VERSION 5.8 ;
BUSBITCHARS "[]" ;
DIVIDERCHAR "/" ;
UNITS
    DATABASE MICRONS 2000 ;
END UNITS

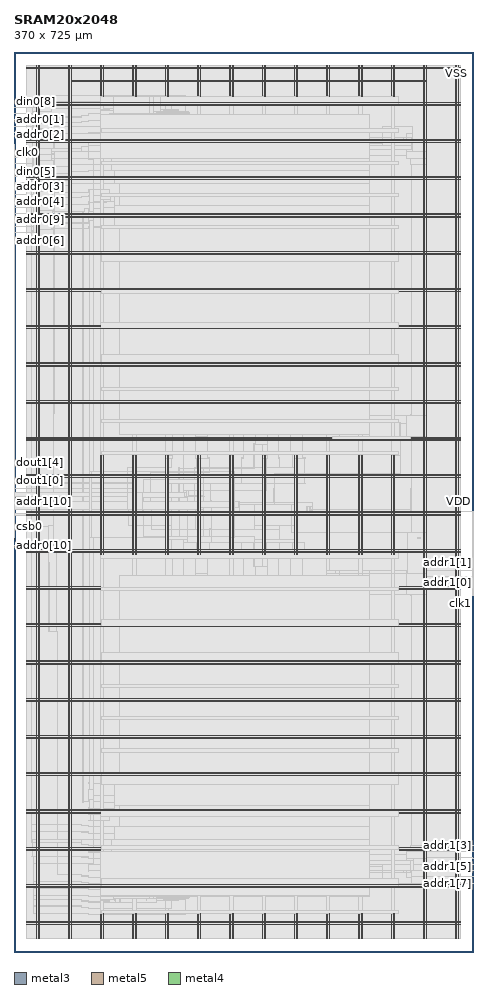
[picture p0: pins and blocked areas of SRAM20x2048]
MACRO SRAM20x2048
  FOREIGN SRAM20x2048 0 0 ;
  CLASS BLOCK ;
  SIZE 370 BY 725 ;
  PIN addr0[0]
    DIRECTION INPUT ;
    USE SIGNAL ;
    PORT
      LAYER metal3 ;
        RECT  0 614.915 0.07 614.985 ;
    END
  END addr0[0]
  PIN addr0[10]
    DIRECTION INPUT ;
    USE SIGNAL ;
    PORT
      LAYER metal3 ;
        RECT  0 327.635 0.07 327.705 ;
    END
  END addr0[10]
  PIN addr0[1]
    DIRECTION INPUT ;
    USE SIGNAL ;
    PORT
      LAYER metal3 ;
        RECT  0 670.355 0.07 670.425 ;
    END
  END addr0[1]
  PIN addr0[2]
    DIRECTION INPUT ;
    USE SIGNAL ;
    PORT
      LAYER metal3 ;
        RECT  0 665.315 0.07 665.385 ;
    END
  END addr0[2]
  PIN addr0[3]
    DIRECTION INPUT ;
    USE SIGNAL ;
    PORT
      LAYER metal3 ;
        RECT  0 609.875 0.07 609.945 ;
    END
  END addr0[3]
  PIN addr0[4]
    DIRECTION INPUT ;
    USE SIGNAL ;
    PORT
      LAYER metal3 ;
        RECT  0 604.835 0.07 604.905 ;
    END
  END addr0[4]
  PIN addr0[5]
    DIRECTION INPUT ;
    USE SIGNAL ;
    PORT
      LAYER metal3 ;
        RECT  0 599.795 0.07 599.865 ;
    END
  END addr0[5]
  PIN addr0[6]
    DIRECTION INPUT ;
    USE SIGNAL ;
    PORT
      LAYER metal3 ;
        RECT  0 579.635 0.07 579.705 ;
    END
  END addr0[6]
  PIN addr0[7]
    DIRECTION INPUT ;
    USE SIGNAL ;
    PORT
      LAYER metal3 ;
        RECT  0 594.755 0.07 594.825 ;
    END
  END addr0[7]
  PIN addr0[8]
    DIRECTION INPUT ;
    USE SIGNAL ;
    PORT
      LAYER metal3 ;
        RECT  0 584.675 0.07 584.745 ;
    END
  END addr0[8]
  PIN addr0[9]
    DIRECTION INPUT ;
    USE SIGNAL ;
    PORT
      LAYER metal3 ;
        RECT  0 589.715 0.07 589.785 ;
    END
  END addr0[9]
  PIN addr1[0]
    DIRECTION INPUT ;
    USE SIGNAL ;
    PORT
      LAYER metal3 ;
        RECT  369.93 297.395 370 297.465 ;
    END
  END addr1[0]
  PIN addr1[10]
    DIRECTION INPUT ;
    USE SIGNAL ;
    PORT
      LAYER metal3 ;
        RECT  0 362.915 0.07 362.985 ;
    END
  END addr1[10]
  PIN addr1[1]
    DIRECTION INPUT ;
    USE SIGNAL ;
    PORT
      LAYER metal3 ;
        RECT  369.93 307.475 370 307.545 ;
    END
  END addr1[1]
  PIN addr1[2]
    DIRECTION INPUT ;
    USE SIGNAL ;
    PORT
      LAYER metal3 ;
        RECT  369.93 302.435 370 302.505 ;
    END
  END addr1[2]
  PIN addr1[3]
    DIRECTION INPUT ;
    USE SIGNAL ;
    PORT
      LAYER metal3 ;
        RECT  369.93 85.715 370 85.785 ;
    END
  END addr1[3]
  PIN addr1[4]
    DIRECTION INPUT ;
    USE SIGNAL ;
    PORT
      LAYER metal3 ;
        RECT  369.93 80.675 370 80.745 ;
    END
  END addr1[4]
  PIN addr1[5]
    DIRECTION INPUT ;
    USE SIGNAL ;
    PORT
      LAYER metal3 ;
        RECT  369.93 75.635 370 75.705 ;
    END
  END addr1[5]
  PIN addr1[6]
    DIRECTION INPUT ;
    USE SIGNAL ;
    PORT
      LAYER metal3 ;
        RECT  369.93 70.595 370 70.665 ;
    END
  END addr1[6]
  PIN addr1[7]
    DIRECTION INPUT ;
    USE SIGNAL ;
    PORT
      LAYER metal3 ;
        RECT  369.93 55.475 370 55.545 ;
    END
  END addr1[7]
  PIN addr1[8]
    DIRECTION INPUT ;
    USE SIGNAL ;
    PORT
      LAYER metal3 ;
        RECT  369.93 65.555 370 65.625 ;
    END
  END addr1[8]
  PIN addr1[9]
    DIRECTION INPUT ;
    USE SIGNAL ;
    PORT
      LAYER metal3 ;
        RECT  369.93 60.515 370 60.585 ;
    END
  END addr1[9]
  PIN clk0
    DIRECTION INPUT ;
    USE SIGNAL ;
    PORT
      LAYER metal3 ;
        RECT  0 650.195 0.07 650.265 ;
    END
  END clk0
  PIN clk1
    DIRECTION INPUT ;
    USE SIGNAL ;
    PORT
      LAYER metal3 ;
        RECT  369.93 287.315 370 287.385 ;
    END
  END clk1
  PIN csb0
    DIRECTION INPUT ;
    USE SIGNAL ;
    PORT
      LAYER metal3 ;
        RECT  0 342.755 0.07 342.825 ;
    END
  END csb0
  PIN csb1
    DIRECTION INPUT ;
    USE SIGNAL ;
    PORT
      LAYER metal3 ;
        RECT  0 357.875 0.07 357.945 ;
    END
  END csb1
  PIN din0[0]
    DIRECTION INPUT ;
    USE SIGNAL ;
    PORT
      LAYER metal3 ;
        RECT  0 675.395 0.07 675.465 ;
    END
  END din0[0]
  PIN din0[1]
    DIRECTION INPUT ;
    USE SIGNAL ;
    PORT
      LAYER metal3 ;
        RECT  0 660.275 0.07 660.345 ;
    END
  END din0[1]
  PIN din0[2]
    DIRECTION INPUT ;
    USE SIGNAL ;
    PORT
      LAYER metal3 ;
        RECT  0 645.155 0.07 645.225 ;
    END
  END din0[2]
  PIN din0[3]
    DIRECTION INPUT ;
    USE SIGNAL ;
    PORT
      LAYER metal3 ;
        RECT  0 640.115 0.07 640.185 ;
    END
  END din0[3]
  PIN din0[4]
    DIRECTION INPUT ;
    USE SIGNAL ;
    PORT
      LAYER metal3 ;
        RECT  0 680.435 0.07 680.505 ;
    END
  END din0[4]
  PIN din0[5]
    DIRECTION INPUT ;
    USE SIGNAL ;
    PORT
      LAYER metal3 ;
        RECT  0 635.075 0.07 635.145 ;
    END
  END din0[5]
  PIN din0[6]
    DIRECTION INPUT ;
    USE SIGNAL ;
    PORT
      LAYER metal3 ;
        RECT  0 630.035 0.07 630.105 ;
    END
  END din0[6]
  PIN din0[7]
    DIRECTION INPUT ;
    USE SIGNAL ;
    PORT
      LAYER metal3 ;
        RECT  0 624.995 0.07 625.065 ;
    END
  END din0[7]
  PIN din0[8]
    DIRECTION INPUT ;
    USE SIGNAL ;
    PORT
      LAYER metal3 ;
        RECT  0 685.475 0.07 685.545 ;
    END
  END din0[8]
  PIN din0[9]
    DIRECTION INPUT ;
    USE SIGNAL ;
    PORT
      LAYER metal3 ;
        RECT  0 619.955 0.07 620.025 ;
    END
  END din0[9]
  PIN dout1[0]
    DIRECTION OUTPUT ;
    USE SIGNAL ;
    PORT
      LAYER metal3 ;
        RECT  0 372.995 0.07 373.065 ;
    END
  END dout1[0]
  PIN dout1[1]
    DIRECTION OUTPUT ;
    USE SIGNAL ;
    PORT
      LAYER metal3 ;
        RECT  0 378.035 0.07 378.105 ;
    END
  END dout1[1]
  PIN dout1[2]
    DIRECTION OUTPUT ;
    USE SIGNAL ;
    PORT
      LAYER metal3 ;
        RECT  0 332.675 0.07 332.745 ;
    END
  END dout1[2]
  PIN dout1[3]
    DIRECTION OUTPUT ;
    USE SIGNAL ;
    PORT
      LAYER metal3 ;
        RECT  0 352.835 0.07 352.905 ;
    END
  END dout1[3]
  PIN dout1[4]
    DIRECTION OUTPUT ;
    USE SIGNAL ;
    PORT
      LAYER metal3 ;
        RECT  0 388.115 0.07 388.185 ;
    END
  END dout1[4]
  PIN dout1[5]
    DIRECTION OUTPUT ;
    USE SIGNAL ;
    PORT
      LAYER metal3 ;
        RECT  0 337.715 0.07 337.785 ;
    END
  END dout1[5]
  PIN dout1[6]
    DIRECTION OUTPUT ;
    USE SIGNAL ;
    PORT
      LAYER metal3 ;
        RECT  0 393.155 0.07 393.225 ;
    END
  END dout1[6]
  PIN dout1[7]
    DIRECTION OUTPUT ;
    USE SIGNAL ;
    PORT
      LAYER metal3 ;
        RECT  0 347.795 0.07 347.865 ;
    END
  END dout1[7]
  PIN dout1[8]
    DIRECTION OUTPUT ;
    USE SIGNAL ;
    PORT
      LAYER metal3 ;
        RECT  0 383.075 0.07 383.145 ;
    END
  END dout1[8]
  PIN dout1[9]
    DIRECTION OUTPUT ;
    USE SIGNAL ;
    PORT
      LAYER metal3 ;
        RECT  0 367.955 0.07 368.025 ;
    END
  END dout1[9]
  PIN VSS
    DIRECTION INOUT ;
    USE GROUND ;
    PORT
      LAYER metal5 ;
        RECT  310.43 531.95 359.86 532.45 ;
        RECT  310.43 291.95 359.86 292.45 ;
        RECT  310.43 111.95 359.86 112.45 ;
        RECT  310.43 81.95 359.86 82.45 ;
        RECT  10.07 711.95 359.86 712.45 ;
        RECT  10.07 681.95 359.86 682.45 ;
        RECT  10.07 651.95 359.86 652.45 ;
        RECT  10.07 621.95 359.86 622.45 ;
        RECT  10.07 591.95 359.86 592.45 ;
        RECT  10.07 561.95 359.86 562.45 ;
        RECT  10.07 531.95 69.32 532.45 ;
        RECT  10.07 501.95 359.86 502.45 ;
        RECT  10.07 471.95 359.86 472.45 ;
        RECT  10.07 441.95 359.86 442.45 ;
        RECT  10.07 411.95 359.86 412.45 ;
        RECT  10.07 381.95 359.86 382.45 ;
        RECT  10.07 351.95 359.86 352.45 ;
        RECT  10.07 321.95 359.86 322.45 ;
        RECT  10.07 291.95 69.32 292.45 ;
        RECT  10.07 261.95 359.86 262.45 ;
        RECT  10.07 231.95 359.86 232.45 ;
        RECT  10.07 201.95 359.86 202.45 ;
        RECT  10.07 171.95 359.86 172.45 ;
        RECT  10.07 141.95 359.86 142.45 ;
        RECT  10.07 111.95 69.57 112.45 ;
        RECT  10.07 81.95 69.32 82.45 ;
        RECT  10.07 51.95 359.86 52.45 ;
        RECT  10.07 21.95 359.86 22.45 ;
      LAYER metal4 ;
        RECT  355.82 11.13 356.32 714.07 ;
        RECT  329.82 11.13 330.32 714.07 ;
        RECT  303.82 689.59 304.32 714.07 ;
        RECT  303.82 320.23 304.32 399.79 ;
        RECT  303.82 11.13 304.32 30.43 ;
        RECT  277.82 689.59 278.32 714.07 ;
        RECT  277.82 320.23 278.32 399.79 ;
        RECT  277.82 11.13 278.32 30.43 ;
        RECT  251.82 689.59 252.32 714.07 ;
        RECT  251.82 320.23 252.32 399.79 ;
        RECT  251.82 11.13 252.32 30.43 ;
        RECT  225.82 689.59 226.32 714.07 ;
        RECT  225.82 320.23 226.32 399.79 ;
        RECT  225.82 11.13 226.32 30.43 ;
        RECT  199.82 689.59 200.32 714.07 ;
        RECT  199.82 320.23 200.32 399.79 ;
        RECT  199.82 11.13 200.32 30.43 ;
        RECT  173.82 689.59 174.32 714.07 ;
        RECT  173.82 320.23 174.32 399.79 ;
        RECT  173.82 11.13 174.32 30.43 ;
        RECT  147.82 689.59 148.32 714.07 ;
        RECT  147.82 320.23 148.32 399.79 ;
        RECT  147.82 11.13 148.32 30.43 ;
        RECT  121.82 689.59 122.32 714.07 ;
        RECT  121.82 320.23 122.32 399.79 ;
        RECT  121.82 11.13 122.32 30.43 ;
        RECT  95.82 689.59 96.32 714.07 ;
        RECT  95.82 320.23 96.32 399.79 ;
        RECT  95.82 11.13 96.32 30.43 ;
        RECT  69.82 689.59 70.32 714.07 ;
        RECT  69.82 320.23 70.32 399.79 ;
        RECT  69.82 11.13 70.32 30.43 ;
        RECT  43.82 11.13 44.32 714.07 ;
        RECT  17.82 11.13 18.32 714.07 ;
    END
  END VSS
  PIN VDD
    DIRECTION INOUT ;
    USE POWER ;
    PORT
      LAYER metal5 ;
        RECT  45.92 701.5 332.42 702 ;
        RECT  320.175 414.05 359.86 414.55 ;
        RECT  310.43 504.05 359.86 504.55 ;
        RECT  310.43 294.05 359.86 294.55 ;
        RECT  310.43 264.05 359.86 264.55 ;
        RECT  310.43 84.05 359.86 84.55 ;
        RECT  10.07 684.05 359.86 684.55 ;
        RECT  10.07 654.05 359.86 654.55 ;
        RECT  10.07 624.05 359.86 624.55 ;
        RECT  10.07 594.05 359.86 594.55 ;
        RECT  10.07 564.05 359.86 564.55 ;
        RECT  10.07 534.05 359.86 534.55 ;
        RECT  10.07 504.05 69.57 504.55 ;
        RECT  10.07 474.05 359.86 474.55 ;
        RECT  10.07 444.05 359.86 444.55 ;
        RECT  10.07 414.05 255.935 414.55 ;
        RECT  10.07 384.05 359.86 384.55 ;
        RECT  10.07 354.05 359.86 354.55 ;
        RECT  10.07 324.05 359.86 324.55 ;
        RECT  10.07 294.05 69.57 294.55 ;
        RECT  10.07 264.05 69.32 264.55 ;
        RECT  10.07 234.05 359.86 234.55 ;
        RECT  10.07 204.05 359.86 204.55 ;
        RECT  10.07 174.05 359.86 174.55 ;
        RECT  10.07 144.05 359.86 144.55 ;
        RECT  10.07 114.05 359.86 114.55 ;
        RECT  10.07 84.05 69.57 84.55 ;
        RECT  10.07 54.05 359.86 54.55 ;
        RECT  10.07 24.05 359.86 24.55 ;
      LAYER metal4 ;
        RECT  357.92 11.16 358.42 714.04 ;
        RECT  331.92 11.16 332.42 714.04 ;
        RECT  305.92 689.38 306.42 714.04 ;
        RECT  305.92 320.2 306.42 399.82 ;
        RECT  305.92 11.16 306.42 30.64 ;
        RECT  279.92 689.38 280.42 714.04 ;
        RECT  279.92 320.2 280.42 399.82 ;
        RECT  279.92 11.16 280.42 30.64 ;
        RECT  253.92 689.38 254.42 714.04 ;
        RECT  253.92 320.2 254.42 399.82 ;
        RECT  253.92 11.16 254.42 30.64 ;
        RECT  227.92 689.38 228.42 714.04 ;
        RECT  227.92 320.2 228.42 399.82 ;
        RECT  227.92 11.16 228.42 30.64 ;
        RECT  201.92 689.38 202.42 714.04 ;
        RECT  201.92 320.2 202.42 399.82 ;
        RECT  201.92 11.16 202.42 30.64 ;
        RECT  175.92 689.38 176.42 714.04 ;
        RECT  175.92 320.2 176.42 399.82 ;
        RECT  175.92 11.16 176.42 30.64 ;
        RECT  149.92 689.38 150.42 714.04 ;
        RECT  149.92 320.2 150.42 399.82 ;
        RECT  149.92 11.16 150.42 30.64 ;
        RECT  123.92 689.38 124.42 714.04 ;
        RECT  123.92 320.2 124.42 399.82 ;
        RECT  123.92 11.16 124.42 30.64 ;
        RECT  97.92 689.38 98.42 714.04 ;
        RECT  97.92 320.2 98.42 399.82 ;
        RECT  97.92 11.16 98.42 30.64 ;
        RECT  71.92 689.38 72.42 714.04 ;
        RECT  71.92 320.2 72.42 399.82 ;
        RECT  71.92 11.16 72.42 30.64 ;
        RECT  45.92 11.16 46.42 714.04 ;
        RECT  19.92 11.16 20.42 714.04 ;
    END
  END VDD
  OBS
    LAYER metal1 ;
     RECT  10.07 11.115 359.86 714.085 ;
    LAYER metal2 ;
     RECT  17.84 11.13 18.3 12.53 ;
     RECT  43.84 11.13 44.3 12.53 ;
     RECT  69.84 11.13 70.3 12.53 ;
     RECT  95.84 11.13 96.3 12.53 ;
     RECT  121.84 11.13 122.3 12.53 ;
     RECT  147.84 11.13 148.3 12.53 ;
     RECT  173.84 11.13 174.3 12.53 ;
     RECT  199.84 11.13 200.3 12.53 ;
     RECT  225.84 11.13 226.3 12.53 ;
     RECT  251.84 11.13 252.3 12.53 ;
     RECT  277.84 11.13 278.3 12.53 ;
     RECT  303.84 11.13 304.3 12.53 ;
     RECT  329.84 11.13 330.3 12.53 ;
     RECT  355.84 11.13 356.3 12.53 ;
     RECT  69.84 12.53 72.4 28.07 ;
     RECT  95.84 12.53 98.4 28.07 ;
     RECT  121.84 12.53 124.4 28.07 ;
     RECT  147.84 12.53 150.4 28.07 ;
     RECT  173.84 12.53 176.4 28.07 ;
     RECT  199.84 12.53 202.4 28.07 ;
     RECT  225.84 12.53 228.4 28.07 ;
     RECT  251.84 12.53 254.4 28.07 ;
     RECT  277.84 12.53 280.4 28.07 ;
     RECT  303.84 12.53 306.4 28.07 ;
     RECT  17.84 12.53 20.4 31.22 ;
     RECT  69.88 28.07 72.4 32.55 ;
     RECT  95.88 28.07 98.4 32.55 ;
     RECT  121.88 28.07 124.4 32.55 ;
     RECT  147.88 28.07 150.4 32.55 ;
     RECT  173.88 28.07 176.4 32.55 ;
     RECT  199.88 28.07 202.4 32.55 ;
     RECT  225.88 28.07 228.4 32.55 ;
     RECT  251.88 28.07 254.4 32.55 ;
     RECT  277.88 28.07 280.4 32.55 ;
     RECT  303.88 28.07 306.4 32.55 ;
     RECT  69.88 32.55 72.44 42.49 ;
     RECT  95.88 32.55 98.44 45.16 ;
     RECT  121.88 32.55 124.44 45.16 ;
     RECT  147.88 32.55 150.44 45.16 ;
     RECT  173.88 32.55 176.44 45.16 ;
     RECT  199.88 32.55 202.44 45.16 ;
     RECT  225.88 32.55 228.44 45.16 ;
     RECT  251.88 32.55 254.44 45.16 ;
     RECT  277.88 32.55 280.44 45.16 ;
     RECT  15.64 31.22 20.4 76.72 ;
     RECT  320.02 77 320.47 85.96 ;
     RECT  14.5 76.72 20.4 87.92 ;
     RECT  34.83 62.58 34.9 258.16 ;
     RECT  34.45 258.16 34.9 258.3 ;
     RECT  320.02 85.96 320.09 293.02 ;
     RECT  319.83 293.02 320.09 299.18 ;
     RECT  319.83 299.18 320.66 301.98 ;
     RECT  85.415 45.16 286.08 303.37 ;
     RECT  70.165 42.49 72.44 305.55 ;
     RECT  316.79 301.98 320.66 307.86 ;
     RECT  28.18 258.16 28.25 313.88 ;
     RECT  69.88 305.55 72.44 318.29 ;
     RECT  95.88 303.37 98.44 318.29 ;
     RECT  147.88 303.37 150.44 318.29 ;
     RECT  173.88 303.37 176.44 318.29 ;
     RECT  225.88 303.37 228.44 318.29 ;
     RECT  251.88 303.37 254.44 318.29 ;
     RECT  277.88 303.37 280.44 318.29 ;
     RECT  303.88 32.55 306.44 318.29 ;
     RECT  225.88 318.29 228.4 319.2 ;
     RECT  69.88 318.29 72.4 321.93 ;
     RECT  95.88 318.29 98.4 321.93 ;
     RECT  121.88 303.37 124.44 321.93 ;
     RECT  147.88 318.29 150.4 321.93 ;
     RECT  173.88 318.29 176.4 321.93 ;
     RECT  199.88 303.37 202.44 321.93 ;
     RECT  251.88 318.29 254.4 321.93 ;
     RECT  277.88 318.29 280.4 321.93 ;
     RECT  303.88 318.29 306.4 321.93 ;
     RECT  121.84 321.93 124.44 322 ;
     RECT  147.84 321.93 150.4 322 ;
     RECT  199.84 321.93 202.44 322 ;
     RECT  27.99 314.16 28.06 327.32 ;
     RECT  34.45 258.3 34.52 327.32 ;
     RECT  27.99 327.32 34.52 327.74 ;
     RECT  234.33 322 234.4 329.95 ;
     RECT  157.38 322 157.45 329.98 ;
     RECT  234.14 329.95 234.4 330.02 ;
     RECT  136.86 319.2 136.93 330.12 ;
     RECT  234.14 330.02 234.21 330.12 ;
     RECT  199.84 322 203.62 330.26 ;
     RECT  325.53 287.14 325.6 330.82 ;
     RECT  147.12 322 150.4 331.94 ;
     RECT  121.84 322 126.67 332.08 ;
     RECT  224.07 319.2 228.4 332.08 ;
     RECT  183.03 322 183.1 332.22 ;
     RECT  320.02 307.86 320.66 333.415 ;
     RECT  173.84 321.93 176.4 333.48 ;
     RECT  325.15 330.96 325.22 333.48 ;
     RECT  173.84 333.48 177.59 333.62 ;
     RECT  173.84 333.62 177.21 333.9 ;
     RECT  136.86 330.12 139.78 334.74 ;
     RECT  193.29 310.66 193.36 334.88 ;
     RECT  147.12 331.94 152.89 335.02 ;
     RECT  225.84 332.08 228.4 337.54 ;
     RECT  0.06 332.64 0.13 337.68 ;
     RECT  223.69 337.54 228.4 338.1 ;
     RECT  147.84 335.02 152.89 340.48 ;
     RECT  213.81 322 213.88 340.62 ;
     RECT  157.38 329.98 159.16 340.76 ;
     RECT  27.99 327.74 31.86 343.28 ;
     RECT  95.84 321.93 98.4 343.28 ;
     RECT  0.06 337.68 0.32 347.76 ;
     RECT  193.86 343.28 193.93 350.28 ;
     RECT  104.56 334.88 104.63 351.54 ;
     RECT  104.56 351.54 105.01 351.68 ;
     RECT  92.02 343.28 98.4 351.82 ;
     RECT  133.44 334.74 139.78 351.96 ;
     RECT  104.56 351.68 104.63 352.1 ;
     RECT  103.8 352.1 104.63 352.24 ;
     RECT  133.44 351.96 133.89 353.36 ;
     RECT  320.02 333.415 320.85 353.365 ;
     RECT  132.87 353.36 133.89 353.5 ;
     RECT  238.13 354.9 238.96 355.18 ;
     RECT  238.13 355.18 240.48 355.88 ;
     RECT  146.36 340.48 152.89 356.16 ;
     RECT  145.79 356.16 152.89 356.3 ;
     RECT  0.06 347.76 0.51 356.44 ;
     RECT  237.75 355.88 240.48 356.44 ;
     RECT  110.83 340.62 110.9 357.14 ;
     RECT  0.06 356.44 0.13 357.28 ;
     RECT  110.83 357.14 111.28 357.28 ;
     RECT  110.83 357.28 110.9 357.7 ;
     RECT  132.68 353.5 132.94 357.7 ;
     RECT  110.07 357.7 110.9 357.84 ;
     RECT  181.89 354.9 181.96 357.84 ;
     RECT  235.47 356.44 240.48 358.68 ;
     RECT  235.47 358.68 235.54 359.1 ;
     RECT  60.86 360.08 60.93 360.22 ;
     RECT  193.67 350.56 193.74 360.5 ;
     RECT  209.44 360.36 209.51 360.5 ;
     RECT  60.1 360.5 60.17 360.64 ;
     RECT  223.5 338.1 228.4 360.64 ;
     RECT  180.75 357.84 181.96 361.48 ;
     RECT  180.75 361.48 181.58 361.9 ;
     RECT  209.44 360.5 210.84 361.9 ;
     RECT  240.41 358.68 240.48 362.04 ;
     RECT  159.09 340.76 159.16 362.74 ;
     RECT  159.09 362.74 159.54 362.88 ;
     RECT  180.94 361.9 181.58 363.02 ;
     RECT  159.09 362.88 159.16 363.16 ;
     RECT  158.33 363.16 159.16 363.3 ;
     RECT  181.51 363.02 181.58 363.3 ;
     RECT  158.52 363.3 159.16 363.44 ;
     RECT  92.02 351.82 98.74 364.56 ;
     RECT  91.26 364.56 98.74 364.7 ;
     RECT  103.8 352.24 104.06 364.7 ;
     RECT  139.71 351.96 139.78 366.1 ;
     RECT  0.06 362.74 0.13 366.94 ;
     RECT  145.6 356.3 152.89 366.94 ;
     RECT  145.6 366.94 153.27 367.08 ;
     RECT  145.6 367.08 152.89 367.5 ;
     RECT  145.6 367.5 152.32 367.78 ;
     RECT  0.06 366.94 0.32 368.34 ;
     RECT  121.84 332.08 127.05 368.34 ;
     RECT  121.84 368.34 127.43 368.48 ;
     RECT  121.84 368.48 127.05 369.04 ;
     RECT  136.86 366.1 139.78 369.74 ;
     RECT  136.86 369.74 140.16 369.88 ;
     RECT  136.86 369.88 139.78 370.3 ;
     RECT  199.84 330.26 202.4 371.84 ;
     RECT  136.86 370.3 139.21 371.98 ;
     RECT  91.45 364.7 98.74 373.1 ;
     RECT  209.44 361.9 209.89 373.385 ;
     RECT  319.64 353.365 320.85 373.385 ;
     RECT  158.52 363.44 158.59 377.58 ;
     RECT  121.84 369.04 126.48 377.72 ;
     RECT  95.84 373.1 98.74 377.86 ;
     RECT  103.99 364.7 104.06 380.52 ;
     RECT  209.63 373.385 209.89 385.14 ;
     RECT  209.63 385.14 210.27 385.28 ;
     RECT  209.63 385.28 209.89 385.84 ;
     RECT  110.26 357.84 110.33 386.26 ;
     RECT  173.84 333.9 176.4 386.54 ;
     RECT  173.84 386.54 177.59 386.82 ;
     RECT  173.84 386.82 177.24 387.03 ;
     RECT  0.06 368.34 0.51 388.22 ;
     RECT  132.87 357.7 132.94 389.9 ;
     RECT  121.84 377.72 124.4 390 ;
     RECT  225.84 360.64 228.4 390 ;
     RECT  145.79 367.78 152.32 390.04 ;
     RECT  213.775 390 213.915 390.07 ;
     RECT  91.45 373.1 91.52 390.18 ;
     RECT  147.12 390.04 152.32 390.18 ;
     RECT  223.88 390 228.4 390.32 ;
     RECT  325.15 391.3 325.22 391.44 ;
     RECT  0.06 388.22 0.13 393.26 ;
     RECT  320.02 373.385 320.85 393.335 ;
     RECT  69.84 321.93 72.4 397.67 ;
     RECT  95.84 377.86 98.4 397.67 ;
     RECT  121.84 390 126.67 397.67 ;
     RECT  173.84 387.03 176.4 397.67 ;
     RECT  199.84 371.84 203.62 397.67 ;
     RECT  251.84 321.93 254.4 397.67 ;
     RECT  277.84 321.93 280.4 397.67 ;
     RECT  303.84 321.93 306.4 397.67 ;
     RECT  121.88 397.67 126.67 398.02 ;
     RECT  147.12 390.18 150.4 398.02 ;
     RECT  157.38 386.12 157.45 398.02 ;
     RECT  183.03 377.58 183.1 398.02 ;
     RECT  199.88 397.67 203.62 398.02 ;
     RECT  213.81 390.07 213.88 398.02 ;
     RECT  234.33 377.44 234.4 398.02 ;
     RECT  136.86 371.98 136.93 400.82 ;
     RECT  224.07 390.32 228.4 400.82 ;
     RECT  69.88 397.67 72.4 401.73 ;
     RECT  95.88 397.67 98.4 401.73 ;
     RECT  147.88 398.02 150.4 401.73 ;
     RECT  173.88 397.67 176.4 401.73 ;
     RECT  225.88 400.82 228.4 401.73 ;
     RECT  251.88 397.67 254.4 401.73 ;
     RECT  277.88 397.67 280.4 401.73 ;
     RECT  303.88 397.67 306.4 401.73 ;
     RECT  193.29 389.76 193.36 409.36 ;
     RECT  69.88 401.73 72.44 414.47 ;
     RECT  95.88 401.73 98.44 416.65 ;
     RECT  121.88 398.02 124.44 416.65 ;
     RECT  147.88 401.73 150.44 416.65 ;
     RECT  173.88 401.73 176.44 416.65 ;
     RECT  199.88 398.02 202.44 416.65 ;
     RECT  225.88 401.73 228.44 416.65 ;
     RECT  251.88 401.73 254.44 416.65 ;
     RECT  277.88 401.73 280.44 416.65 ;
     RECT  320.02 393.335 320.66 426.02 ;
     RECT  310.9 414.96 310.97 426.16 ;
     RECT  319.26 426.02 320.66 427 ;
     RECT  325.53 391.58 325.6 432.88 ;
     RECT  31.6 343.28 31.86 433.44 ;
     RECT  32.17 433.72 32.24 582.12 ;
     RECT  30.08 582.12 32.24 583.1 ;
     RECT  32.17 583.1 32.24 587.16 ;
     RECT  30.84 587.16 32.24 587.3 ;
     RECT  30.08 587.3 32.24 587.44 ;
     RECT  32.17 587.44 32.24 591.92 ;
     RECT  30.08 591.92 32.24 593.04 ;
     RECT  61.24 587.02 61.31 594.02 ;
     RECT  55.54 120.82 55.61 596.68 ;
     RECT  55.54 596.68 56.56 596.82 ;
     RECT  30.84 593.04 32.24 596.96 ;
     RECT  30.08 596.96 32.24 597.1 ;
     RECT  56.49 596.82 56.56 599.2 ;
     RECT  32.17 597.1 32.24 601.16 ;
     RECT  30.08 601.16 32.24 602.7 ;
     RECT  32.17 602.7 32.24 606.9 ;
     RECT  30.08 606.9 32.24 608.3 ;
     RECT  30.84 608.3 32.24 612.5 ;
     RECT  30.08 612.5 32.24 612.64 ;
     RECT  32.17 612.64 32.24 617.12 ;
     RECT  30.08 617.12 32.24 618.24 ;
     RECT  30.46 618.24 32.24 622.16 ;
     RECT  30.08 622.16 32.24 622.3 ;
     RECT  32.17 622.3 32.24 626.92 ;
     RECT  30.08 626.92 32.24 627.9 ;
     RECT  14.31 87.92 20.4 630.14 ;
     RECT  32.17 627.9 32.24 632.52 ;
     RECT  30.08 632.52 32.24 633.5 ;
     RECT  32.17 633.5 32.24 637.7 ;
     RECT  30.08 637.7 32.24 637.84 ;
     RECT  320.02 427 320.66 638.12 ;
     RECT  319.83 638.12 320.66 638.54 ;
     RECT  14.5 630.14 20.4 640.22 ;
     RECT  30.46 637.84 32.24 642.32 ;
     RECT  30.08 642.32 32.24 643.44 ;
     RECT  30.46 643.44 32.24 647.36 ;
     RECT  30.08 647.36 32.24 647.5 ;
     RECT  14.88 640.22 20.4 652.685 ;
     RECT  319.83 638.54 320.09 653.94 ;
     RECT  320.02 653.94 320.09 659.54 ;
     RECT  32.17 647.5 32.24 659.68 ;
     RECT  15.45 652.685 20.4 660.24 ;
     RECT  30.08 662.9 30.53 663.04 ;
     RECT  30.46 663.04 30.53 667.52 ;
     RECT  30.08 667.52 30.53 668.08 ;
     RECT  30.08 668.08 30.15 668.64 ;
     RECT  30.08 672.56 30.53 672.7 ;
     RECT  85.415 416.65 286.08 674.86 ;
     RECT  70.165 414.47 72.44 677.53 ;
     RECT  30.08 677.32 30.15 678.16 ;
     RECT  30.08 678.16 30.53 678.3 ;
     RECT  30.46 678.3 30.53 679.84 ;
     RECT  30.08 682.92 30.15 683.9 ;
     RECT  69.88 677.53 72.44 687.47 ;
     RECT  95.88 674.86 98.44 687.47 ;
     RECT  121.88 674.86 124.44 687.47 ;
     RECT  147.88 674.86 150.44 687.47 ;
     RECT  173.88 674.86 176.44 687.47 ;
     RECT  199.88 674.86 202.44 687.47 ;
     RECT  225.88 674.86 228.44 687.47 ;
     RECT  251.88 674.86 254.44 687.47 ;
     RECT  277.88 674.86 280.44 687.47 ;
     RECT  303.88 401.73 306.44 687.47 ;
     RECT  30.46 683.9 30.53 688.1 ;
     RECT  15.26 660.24 20.4 688.24 ;
     RECT  30.08 688.1 30.53 688.24 ;
     RECT  30.46 688.24 30.53 689.92 ;
     RECT  69.88 687.47 72.4 691.53 ;
     RECT  95.88 687.47 98.4 691.53 ;
     RECT  121.88 687.47 124.4 691.53 ;
     RECT  147.88 687.47 150.4 691.53 ;
     RECT  173.88 687.47 176.4 691.53 ;
     RECT  199.88 687.47 202.4 691.53 ;
     RECT  225.88 687.47 228.4 691.53 ;
     RECT  251.88 687.47 254.4 691.53 ;
     RECT  277.88 687.47 280.4 691.53 ;
     RECT  303.88 687.47 306.4 691.53 ;
     RECT  17.84 688.24 20.4 712.67 ;
     RECT  43.84 12.53 46.4 712.67 ;
     RECT  69.84 691.53 72.4 712.67 ;
     RECT  95.84 691.53 98.4 712.67 ;
     RECT  121.84 691.53 124.4 712.67 ;
     RECT  147.84 691.53 150.4 712.67 ;
     RECT  173.84 691.53 176.4 712.67 ;
     RECT  199.84 691.53 202.4 712.67 ;
     RECT  225.84 691.53 228.4 712.67 ;
     RECT  251.84 691.53 254.4 712.67 ;
     RECT  277.84 691.53 280.4 712.67 ;
     RECT  303.84 691.53 306.4 712.67 ;
     RECT  329.84 12.53 332.4 712.67 ;
     RECT  355.84 12.53 358.4 712.67 ;
     RECT  17.84 712.67 18.3 714.07 ;
     RECT  43.84 712.67 44.3 714.07 ;
     RECT  69.84 712.67 70.3 714.07 ;
     RECT  95.84 712.67 96.3 714.07 ;
     RECT  121.84 712.67 122.3 714.07 ;
     RECT  147.84 712.67 148.3 714.07 ;
     RECT  173.84 712.67 174.3 714.07 ;
     RECT  199.84 712.67 200.3 714.07 ;
     RECT  225.84 712.67 226.3 714.07 ;
     RECT  251.84 712.67 252.3 714.07 ;
     RECT  277.84 712.67 278.3 714.07 ;
     RECT  303.84 712.67 304.3 714.07 ;
     RECT  329.84 712.67 330.3 714.07 ;
     RECT  355.84 712.67 356.3 714.07 ;
    LAYER metal3 ;
     RECT  0 327.355 0.035 327.565 ;
     RECT  0.025 357.175 0.035 357.245 ;
     RECT  0.025 360.535 0.035 362.845 ;
     RECT  0 377.755 0.035 377.965 ;
     RECT  0.035 327.355 0.13 327.705 ;
     RECT  0.035 377.755 0.13 378.105 ;
     RECT  0.025 332.675 0.165 332.745 ;
     RECT  0.025 393.155 0.165 393.225 ;
     RECT  0.025 650.195 0.165 650.265 ;
     RECT  0.025 351.575 0.215 352.905 ;
     RECT  0.025 367.955 0.215 369.845 ;
     RECT  0.035 337.715 0.355 337.785 ;
     RECT  0.035 383.075 0.355 383.145 ;
     RECT  0.035 357.175 0.405 362.985 ;
     RECT  0.035 347.795 0.545 347.865 ;
     RECT  0.035 388.115 0.545 388.185 ;
     RECT  0.035 579.635 14.845 579.705 ;
     RECT  14.275 87.955 15.035 88.025 ;
     RECT  14.845 579.635 15.605 580.965 ;
     RECT  0.035 584.675 15.605 584.745 ;
     RECT  0.035 589.715 15.605 589.785 ;
     RECT  0.035 594.755 15.605 594.825 ;
     RECT  0.035 599.795 15.605 599.865 ;
     RECT  0.035 604.835 15.605 604.905 ;
     RECT  0.035 609.875 15.605 609.945 ;
     RECT  0.035 614.915 15.605 614.985 ;
     RECT  0.035 619.955 15.605 620.025 ;
     RECT  0.035 624.995 15.605 625.065 ;
     RECT  0.035 630.035 15.605 630.105 ;
     RECT  0.035 635.075 15.605 635.145 ;
     RECT  0.035 640.115 15.605 640.185 ;
     RECT  0.035 645.155 15.605 645.225 ;
     RECT  0.035 660.275 15.605 660.345 ;
     RECT  0.035 665.315 15.605 665.385 ;
     RECT  0.035 670.355 15.605 670.425 ;
     RECT  0.035 675.395 15.605 675.465 ;
     RECT  0.035 680.435 15.605 680.505 ;
     RECT  0.035 685.475 15.605 685.545 ;
     RECT  15.605 31.255 17.84 31.325 ;
     RECT  15.795 36.995 17.84 37.065 ;
     RECT  15.985 42.595 17.84 42.665 ;
     RECT  16.175 45.535 17.84 45.605 ;
     RECT  16.365 51.135 17.84 51.205 ;
     RECT  16.555 56.875 17.84 56.945 ;
     RECT  16.745 71.155 17.84 71.225 ;
     RECT  14.465 76.755 17.84 76.825 ;
     RECT  15.415 82.355 17.84 82.425 ;
     RECT  15.035 87.955 17.84 90.825 ;
     RECT  14.845 96.775 17.84 96.845 ;
     RECT  14.655 102.515 17.84 102.585 ;
     RECT  0.13 327.355 17.84 327.425 ;
     RECT  0.035 342.755 17.84 342.825 ;
     RECT  0.215 351.575 17.84 353.465 ;
     RECT  0.405 356.335 17.84 362.985 ;
     RECT  0.215 366.975 17.84 369.845 ;
     RECT  0.035 372.995 17.84 373.065 ;
     RECT  0.13 377.755 17.84 377.825 ;
     RECT  14.845 572.915 17.84 572.985 ;
     RECT  15.605 579.635 17.84 601.265 ;
     RECT  15.605 604.835 17.84 607.005 ;
     RECT  15.605 609.875 17.84 627.025 ;
     RECT  15.605 630.035 17.84 647.465 ;
     RECT  15.605 660.275 17.84 677.425 ;
     RECT  15.605 680.435 17.84 688.205 ;
     RECT  17.84 11.13 18.3 714.07 ;
     RECT  18.3 12.53 20.4 712.67 ;
     RECT  20.4 342.755 27.955 342.825 ;
     RECT  27.955 342.755 28.095 343.245 ;
     RECT  20.4 582.155 30.185 582.225 ;
     RECT  20.4 587.335 30.185 587.405 ;
     RECT  20.4 591.955 30.185 592.025 ;
     RECT  20.4 596.995 30.185 597.065 ;
     RECT  20.4 601.195 30.185 601.265 ;
     RECT  20.4 606.935 30.185 607.005 ;
     RECT  20.4 612.535 30.185 612.605 ;
     RECT  20.4 617.155 30.185 617.225 ;
     RECT  20.4 622.195 30.185 622.265 ;
     RECT  20.4 626.955 30.185 627.025 ;
     RECT  20.4 632.555 30.185 632.625 ;
     RECT  20.4 637.735 30.185 637.805 ;
     RECT  20.4 642.355 30.185 642.425 ;
     RECT  20.4 647.395 30.185 647.465 ;
     RECT  20.4 662.935 30.185 663.005 ;
     RECT  20.4 667.555 30.185 667.625 ;
     RECT  20.4 677.355 30.185 677.425 ;
     RECT  20.4 682.955 30.185 683.025 ;
     RECT  20.4 688.135 30.185 688.205 ;
     RECT  28.095 343.175 31.705 343.245 ;
     RECT  20.4 327.355 34.165 327.425 ;
     RECT  34.165 327.355 34.235 327.705 ;
     RECT  34.235 327.635 34.555 327.705 ;
     RECT  28.145 258.195 34.935 258.265 ;
     RECT  20.4 31.255 43.84 31.325 ;
     RECT  20.4 36.995 43.84 37.065 ;
     RECT  20.4 42.595 43.84 42.665 ;
     RECT  20.4 45.535 43.84 45.605 ;
     RECT  20.4 51.135 43.84 51.205 ;
     RECT  20.4 56.875 43.84 56.945 ;
     RECT  34.795 62.615 43.84 62.685 ;
     RECT  20.4 71.155 43.84 71.225 ;
     RECT  20.4 76.755 43.84 76.825 ;
     RECT  20.4 82.355 43.84 82.425 ;
     RECT  20.4 87.955 43.84 90.825 ;
     RECT  20.4 96.775 43.84 96.845 ;
     RECT  20.4 102.515 43.84 102.585 ;
     RECT  20.4 351.575 43.84 353.465 ;
     RECT  20.4 356.335 43.84 362.985 ;
     RECT  20.4 366.975 43.84 369.845 ;
     RECT  20.4 372.995 43.84 373.065 ;
     RECT  20.4 377.755 43.84 377.825 ;
     RECT  30.805 582.715 43.84 582.785 ;
     RECT  30.805 587.195 43.84 587.265 ;
     RECT  30.805 592.795 43.84 592.865 ;
     RECT  30.805 596.715 43.84 596.785 ;
     RECT  30.805 602.315 43.84 602.385 ;
     RECT  30.805 607.915 43.84 607.985 ;
     RECT  30.805 612.115 43.84 612.185 ;
     RECT  30.425 617.575 43.84 617.645 ;
     RECT  30.425 621.775 43.84 621.845 ;
     RECT  30.425 627.375 43.84 627.445 ;
     RECT  30.425 632.975 43.84 633.045 ;
     RECT  30.425 639.415 43.84 639.485 ;
     RECT  30.425 644.455 43.84 647.045 ;
     RECT  32.135 659.575 43.84 659.645 ;
     RECT  30.425 664.615 43.84 664.685 ;
     RECT  30.425 667.975 43.84 668.045 ;
     RECT  20.4 672.595 43.84 672.665 ;
     RECT  30.425 679.735 43.84 679.805 ;
     RECT  30.425 684.775 43.84 684.845 ;
     RECT  30.425 689.815 43.84 689.885 ;
     RECT  43.84 11.13 44.3 714.07 ;
     RECT  44.3 12.53 46.4 712.67 ;
     RECT  46.4 31.255 54.115 31.325 ;
     RECT  46.4 36.995 54.115 37.065 ;
     RECT  46.4 42.595 54.115 42.665 ;
     RECT  46.4 56.875 54.115 56.945 ;
     RECT  46.4 62.615 54.115 62.685 ;
     RECT  46.4 76.755 54.115 76.825 ;
     RECT  46.4 82.355 54.115 82.425 ;
     RECT  46.4 87.955 54.115 90.825 ;
     RECT  46.4 96.775 54.115 96.845 ;
     RECT  46.4 102.515 54.115 102.585 ;
     RECT  46.4 582.715 54.115 582.785 ;
     RECT  46.4 592.795 54.115 592.865 ;
     RECT  46.4 607.915 54.115 607.985 ;
     RECT  46.4 644.455 54.115 647.045 ;
     RECT  46.4 667.975 54.115 668.045 ;
     RECT  46.4 672.595 54.115 672.665 ;
     RECT  54.115 31.115 54.185 31.325 ;
     RECT  54.115 35.875 54.185 37.065 ;
     RECT  54.115 41.055 54.185 42.665 ;
     RECT  54.115 56.315 54.185 56.945 ;
     RECT  54.115 61.215 54.185 62.685 ;
     RECT  54.115 76.475 54.185 76.825 ;
     RECT  54.115 81.375 54.185 82.425 ;
     RECT  54.115 86.275 54.185 90.825 ;
     RECT  54.115 96.635 54.185 96.845 ;
     RECT  54.115 101.535 54.185 102.585 ;
     RECT  54.115 582.715 54.185 583.205 ;
     RECT  54.115 592.795 54.185 593.145 ;
     RECT  54.115 607.915 54.185 608.405 ;
     RECT  54.115 644.455 54.185 648.725 ;
     RECT  54.115 667.975 54.185 669.025 ;
     RECT  54.115 672.595 54.185 673.925 ;
     RECT  46.4 596.715 56.455 596.785 ;
     RECT  56.455 596.715 56.595 599.165 ;
     RECT  54.185 31.115 60.04 31.185 ;
     RECT  54.185 35.875 60.04 35.945 ;
     RECT  54.185 41.055 60.04 41.125 ;
     RECT  46.4 45.535 60.04 45.605 ;
     RECT  46.4 51.135 60.04 51.205 ;
     RECT  54.185 56.315 60.04 56.385 ;
     RECT  54.185 61.215 60.04 61.285 ;
     RECT  46.4 71.155 60.04 71.225 ;
     RECT  54.185 76.475 60.04 76.545 ;
     RECT  54.185 81.375 60.04 81.445 ;
     RECT  54.185 86.275 60.04 86.345 ;
     RECT  54.185 90.755 60.04 90.825 ;
     RECT  54.185 96.635 60.04 96.705 ;
     RECT  54.185 101.535 60.04 101.605 ;
     RECT  54.185 583.135 60.04 583.205 ;
     RECT  46.4 587.195 60.04 587.265 ;
     RECT  54.185 593.075 60.04 593.145 ;
     RECT  46.4 602.315 60.04 602.385 ;
     RECT  54.185 608.335 60.04 608.405 ;
     RECT  46.4 612.115 60.04 612.185 ;
     RECT  46.4 618.975 60.04 619.045 ;
     RECT  46.4 624.295 60.04 624.365 ;
     RECT  46.4 628.775 60.04 628.845 ;
     RECT  54.185 648.655 60.04 648.725 ;
     RECT  54.185 668.955 60.04 669.025 ;
     RECT  54.185 673.855 60.04 673.925 ;
     RECT  55.505 120.855 60.065 120.925 ;
     RECT  60.04 125.895 60.065 126.105 ;
     RECT  60.04 593.075 60.065 594.125 ;
     RECT  56.595 599.095 60.065 599.165 ;
     RECT  60.04 60.375 60.1 61.285 ;
     RECT  46.4 659.575 60.1 659.645 ;
     RECT  60.04 30.135 60.11 31.185 ;
     RECT  60.04 35.175 60.11 35.945 ;
     RECT  60.04 40.215 60.11 41.125 ;
     RECT  60.04 44.695 60.11 45.605 ;
     RECT  60.04 50.295 60.11 51.205 ;
     RECT  60.04 55.335 60.11 56.385 ;
     RECT  60.1 60.235 60.11 61.285 ;
     RECT  60.04 75.495 60.11 76.545 ;
     RECT  60.04 80.535 60.11 81.445 ;
     RECT  60.04 85.575 60.11 86.345 ;
     RECT  60.04 90.615 60.11 90.825 ;
     RECT  60.04 95.375 60.11 96.705 ;
     RECT  60.04 100.695 60.11 101.605 ;
     RECT  60.04 618.975 60.11 619.325 ;
     RECT  60.04 628.775 60.11 629.405 ;
     RECT  60.04 648.655 60.11 649.845 ;
     RECT  60.04 668.955 60.11 669.725 ;
     RECT  60.04 673.855 60.11 675.325 ;
     RECT  60.11 44.695 60.17 45.325 ;
     RECT  60.11 60.235 60.17 60.445 ;
     RECT  60.11 95.375 60.17 95.725 ;
     RECT  60.065 120.855 60.17 126.105 ;
     RECT  60.065 593.075 60.17 599.165 ;
     RECT  60.04 624.295 60.17 624.645 ;
     RECT  60.11 649.495 60.17 649.845 ;
     RECT  60.1 659.575 60.17 659.785 ;
     RECT  60.11 674.695 60.17 675.325 ;
     RECT  60.04 130.795 60.205 131.005 ;
     RECT  60.04 587.195 60.205 589.085 ;
     RECT  60.04 70.175 60.225 71.225 ;
     RECT  46.4 639.415 60.225 639.485 ;
     RECT  60.04 65.275 60.365 65.485 ;
     RECT  60.04 654.395 60.365 654.605 ;
     RECT  60.04 115.815 60.645 116.025 ;
     RECT  60.04 602.315 60.645 604.205 ;
     RECT  60.17 120.995 60.925 126.105 ;
     RECT  60.17 593.075 60.925 599.025 ;
     RECT  60.205 130.795 61.205 130.865 ;
     RECT  60.205 587.195 61.205 588.245 ;
     RECT  60.04 612.115 61.205 614.285 ;
     RECT  60.925 593.915 61.345 599.025 ;
     RECT  60.04 135.975 61.485 136.185 ;
     RECT  60.04 583.135 61.485 584.045 ;
     RECT  60.04 110.775 61.765 110.985 ;
     RECT  60.04 608.335 61.765 609.245 ;
     RECT  60.04 105.735 62.045 105.945 ;
     RECT  61.205 587.055 62.045 587.125 ;
     RECT  60.225 70.175 64.005 71.365 ;
     RECT  60.225 638.295 64.005 639.485 ;
     RECT  60.11 30.135 69.84 30.205 ;
     RECT  63.865 333.515 69.84 333.585 ;
     RECT  46.4 351.575 69.84 353.465 ;
     RECT  46.4 356.335 69.84 362.985 ;
     RECT  46.4 366.975 69.84 369.845 ;
     RECT  46.4 372.995 69.84 373.065 ;
     RECT  46.4 377.755 69.84 377.825 ;
     RECT  63.865 386.715 69.84 386.785 ;
     RECT  46.4 689.815 69.84 689.885 ;
     RECT  69.84 11.13 69.88 30.205 ;
     RECT  60.11 35.175 69.88 35.245 ;
     RECT  60.11 40.215 69.88 40.285 ;
     RECT  60.17 44.695 69.88 44.765 ;
     RECT  69.84 321.93 69.88 397.67 ;
     RECT  60.17 675.255 69.88 675.325 ;
     RECT  46.4 679.735 69.88 679.805 ;
     RECT  46.4 684.775 69.88 684.845 ;
     RECT  69.84 689.815 69.88 714.07 ;
     RECT  69.88 11.13 70.165 44.765 ;
     RECT  60.11 50.295 70.165 50.365 ;
     RECT  60.11 55.335 70.165 55.405 ;
     RECT  60.17 60.235 70.165 60.305 ;
     RECT  60.365 65.415 70.165 65.485 ;
     RECT  64.005 70.175 70.165 70.245 ;
     RECT  60.11 75.495 70.165 75.565 ;
     RECT  60.11 80.535 70.165 80.605 ;
     RECT  60.11 85.575 70.165 85.645 ;
     RECT  60.11 90.615 70.165 90.685 ;
     RECT  60.17 95.375 70.165 95.445 ;
     RECT  60.11 100.695 70.165 100.765 ;
     RECT  62.045 105.735 70.165 105.805 ;
     RECT  61.765 110.775 70.165 110.845 ;
     RECT  60.645 115.815 70.165 115.885 ;
     RECT  60.925 120.995 70.165 125.965 ;
     RECT  61.485 135.975 70.165 136.045 ;
     RECT  69.88 305.55 70.165 414.47 ;
     RECT  61.485 583.975 70.165 584.045 ;
     RECT  61.345 594.055 70.165 599.025 ;
     RECT  60.645 604.135 70.165 604.205 ;
     RECT  61.765 609.175 70.165 609.245 ;
     RECT  61.205 614.215 70.165 614.285 ;
     RECT  60.11 619.255 70.165 619.325 ;
     RECT  60.17 624.575 70.165 624.645 ;
     RECT  60.11 629.335 70.165 629.405 ;
     RECT  46.4 634.375 70.165 634.445 ;
     RECT  64.005 639.415 70.165 639.485 ;
     RECT  54.185 644.455 70.165 644.525 ;
     RECT  60.17 649.775 70.165 649.845 ;
     RECT  60.365 654.535 70.165 654.605 ;
     RECT  60.17 659.715 70.165 659.785 ;
     RECT  46.4 664.615 70.165 664.685 ;
     RECT  60.11 669.655 70.165 669.725 ;
     RECT  69.88 675.255 70.165 714.07 ;
     RECT  70.165 11.13 70.3 714.07 ;
     RECT  70.3 12.53 72.4 712.67 ;
     RECT  72.4 30.135 72.44 318.29 ;
     RECT  72.4 401.73 72.44 689.885 ;
     RECT  72.44 115.675 74.325 115.885 ;
     RECT  72.44 604.135 74.325 604.345 ;
     RECT  72.44 40.215 75.465 40.285 ;
     RECT  72.44 679.735 75.465 679.805 ;
     RECT  72.44 80.535 75.605 80.605 ;
     RECT  72.44 639.415 75.605 639.485 ;
     RECT  75.465 40.215 75.745 41.825 ;
     RECT  72.44 44.695 75.745 44.765 ;
     RECT  72.44 675.255 75.745 675.325 ;
     RECT  75.465 678.195 75.745 679.805 ;
     RECT  72.44 70.175 75.885 70.245 ;
     RECT  72.44 649.775 75.885 649.845 ;
     RECT  72.44 110.775 77.145 110.845 ;
     RECT  72.44 609.175 77.145 609.245 ;
     RECT  75.745 40.215 77.285 44.765 ;
     RECT  72.44 105.735 77.285 105.805 ;
     RECT  72.44 614.215 77.285 614.285 ;
     RECT  75.745 675.255 77.285 679.805 ;
     RECT  77.145 110.635 77.425 110.845 ;
     RECT  74.325 115.675 77.425 115.745 ;
     RECT  74.325 604.275 77.425 604.345 ;
     RECT  77.145 609.175 77.425 609.385 ;
     RECT  72.44 90.615 78.405 90.685 ;
     RECT  72.44 629.335 78.405 629.405 ;
     RECT  72.44 75.495 78.685 75.565 ;
     RECT  72.44 644.455 78.685 644.525 ;
     RECT  72.44 50.295 80.085 50.365 ;
     RECT  72.44 669.655 80.085 669.725 ;
     RECT  72.44 55.335 80.365 55.405 ;
     RECT  72.44 664.615 80.365 664.685 ;
     RECT  77.425 110.635 81.345 115.745 ;
     RECT  72.44 120.575 81.345 125.965 ;
     RECT  72.44 594.055 81.345 599.445 ;
     RECT  77.425 604.275 81.345 609.385 ;
     RECT  72.44 100.695 81.485 100.765 ;
     RECT  72.44 135.975 81.485 136.045 ;
     RECT  72.44 583.975 81.485 584.045 ;
     RECT  72.44 619.255 81.485 619.325 ;
     RECT  77.285 40.215 81.625 42.665 ;
     RECT  77.285 677.355 81.625 679.805 ;
     RECT  72.44 95.375 81.765 95.445 ;
     RECT  72.44 624.575 81.765 624.645 ;
     RECT  72.44 85.575 82.045 85.645 ;
     RECT  72.44 634.375 82.045 634.445 ;
     RECT  81.625 40.215 85.275 42.805 ;
     RECT  72.44 60.095 85.275 60.445 ;
     RECT  81.345 110.635 85.275 125.965 ;
     RECT  81.345 594.055 85.275 609.385 ;
     RECT  72.44 659.575 85.275 659.925 ;
     RECT  81.625 677.215 85.275 679.805 ;
     RECT  85.275 40.215 85.415 45.72 ;
     RECT  85.275 60.06 85.415 60.445 ;
     RECT  85.275 110.63 85.415 125.965 ;
     RECT  85.275 302.81 85.415 303.51 ;
     RECT  85.275 416.51 85.415 417.21 ;
     RECT  85.275 594.055 85.415 609.39 ;
     RECT  85.275 659.575 85.415 659.96 ;
     RECT  85.275 674.3 85.415 679.805 ;
     RECT  72.4 356.335 91.225 362.985 ;
     RECT  72.4 366.975 91.225 369.845 ;
     RECT  72.4 372.995 92.505 373.065 ;
     RECT  72.44 30.135 95.84 30.205 ;
     RECT  72.4 333.515 95.84 333.585 ;
     RECT  91.985 343.315 95.84 343.385 ;
     RECT  72.4 351.575 95.84 353.465 ;
     RECT  91.225 356.335 95.84 369.845 ;
     RECT  72.4 377.755 95.84 377.825 ;
     RECT  72.4 386.715 95.84 386.785 ;
     RECT  91.415 390.075 95.84 390.145 ;
     RECT  72.44 689.815 95.84 689.885 ;
     RECT  95.84 11.13 95.88 30.205 ;
     RECT  72.44 35.175 95.88 35.245 ;
     RECT  85.415 40.215 95.88 303.51 ;
     RECT  95.84 321.93 95.88 397.67 ;
     RECT  85.415 416.51 95.88 679.805 ;
     RECT  72.44 684.775 95.88 684.845 ;
     RECT  95.84 689.815 95.88 714.07 ;
     RECT  95.88 11.13 96.3 714.07 ;
     RECT  96.3 12.53 98.4 712.67 ;
     RECT  98.4 30.135 98.44 318.29 ;
     RECT  98.4 401.73 98.44 689.885 ;
     RECT  98.4 377.755 98.775 377.825 ;
     RECT  98.4 356.335 103.905 369.845 ;
     RECT  98.4 333.515 104.525 333.585 ;
     RECT  98.4 351.575 105.045 353.465 ;
     RECT  98.4 386.715 110.225 386.785 ;
     RECT  98.4 343.315 110.795 343.385 ;
     RECT  98.44 40.215 115.085 303.51 ;
     RECT  98.44 416.51 115.085 679.805 ;
     RECT  98.44 30.135 121.84 30.205 ;
     RECT  104.525 333.515 121.84 334.985 ;
     RECT  110.795 340.655 121.84 343.385 ;
     RECT  105.045 351.855 121.84 353.465 ;
     RECT  103.905 356.335 121.84 362.985 ;
     RECT  103.905 366.135 121.84 369.845 ;
     RECT  103.955 380.415 121.84 380.485 ;
     RECT  110.225 386.155 121.84 386.785 ;
     RECT  98.4 390.075 121.84 390.145 ;
     RECT  98.44 689.815 121.84 689.885 ;
     RECT  121.84 11.13 121.88 30.205 ;
     RECT  98.44 35.175 121.88 35.245 ;
     RECT  115.085 41.615 121.88 303.51 ;
     RECT  121.84 321.93 121.88 397.67 ;
     RECT  115.085 416.51 121.88 678.405 ;
     RECT  98.44 684.775 121.88 684.845 ;
     RECT  121.84 689.815 121.88 714.07 ;
     RECT  121.88 11.13 122.3 714.07 ;
     RECT  122.3 12.53 124.4 712.67 ;
     RECT  124.4 30.135 124.44 318.29 ;
     RECT  124.4 401.73 124.44 689.885 ;
     RECT  124.4 390.075 126.515 390.145 ;
     RECT  124.44 35.175 126.565 35.245 ;
     RECT  124.44 684.775 126.565 684.845 ;
     RECT  124.4 340.655 126.705 343.385 ;
     RECT  124.4 322.035 127.405 322.105 ;
     RECT  124.4 397.915 127.405 397.985 ;
     RECT  124.44 41.615 132.445 303.51 ;
     RECT  124.44 416.51 132.445 678.405 ;
     RECT  124.4 351.855 133.925 353.465 ;
     RECT  132.445 42.595 135.245 303.51 ;
     RECT  132.445 416.51 135.245 677.425 ;
     RECT  136.785 319.235 136.965 319.305 ;
     RECT  133.925 351.855 136.965 351.925 ;
     RECT  124.4 366.135 136.965 370.265 ;
     RECT  136.785 400.715 136.965 400.785 ;
     RECT  124.44 30.135 138.325 30.205 ;
     RECT  124.44 689.815 138.325 689.885 ;
     RECT  136.965 366.975 139.105 370.265 ;
     RECT  124.4 332.115 139.675 334.985 ;
     RECT  139.105 366.975 140.195 371.945 ;
     RECT  135.245 42.735 140.845 303.51 ;
     RECT  135.245 416.51 140.845 677.285 ;
     RECT  132.835 389.795 145.755 389.865 ;
     RECT  126.705 340.655 146.325 340.725 ;
     RECT  146.025 322.035 147.84 322.105 ;
     RECT  139.675 330.155 147.84 334.985 ;
     RECT  146.325 340.515 147.84 340.725 ;
     RECT  124.4 356.335 147.84 362.985 ;
     RECT  140.195 366.975 147.84 367.745 ;
     RECT  140.195 371.875 147.84 371.945 ;
     RECT  124.4 377.615 147.84 380.485 ;
     RECT  124.4 386.155 147.84 386.785 ;
     RECT  145.755 389.795 147.84 390.005 ;
     RECT  146.025 397.915 147.84 397.985 ;
     RECT  140.845 45.02 147.88 303.51 ;
     RECT  147.84 321.93 147.88 397.985 ;
     RECT  140.845 416.51 147.88 675 ;
     RECT  147.84 691.53 147.88 714.07 ;
     RECT  147.84 11.13 148.3 28.07 ;
     RECT  147.88 31.15 148.3 714.07 ;
     RECT  148.3 31.15 148.34 712.67 ;
     RECT  148.3 12.53 149.94 28.07 ;
     RECT  149.94 12.53 150.4 29.47 ;
     RECT  148.34 32.55 150.4 712.67 ;
     RECT  150.4 32.55 150.44 318.29 ;
     RECT  150.4 401.73 150.44 687.47 ;
     RECT  150.4 366.975 151.89 367.745 ;
     RECT  151.89 366.975 152.165 367.605 ;
     RECT  152.165 366.975 153.305 367.045 ;
     RECT  155.545 322.035 157.485 322.105 ;
     RECT  150.4 340.515 157.485 340.725 ;
     RECT  150.4 386.155 157.485 386.785 ;
     RECT  155.545 397.915 157.485 397.985 ;
     RECT  150.4 377.615 158.485 377.685 ;
     RECT  150.4 330.155 159.055 334.845 ;
     RECT  157.485 386.715 173.815 386.785 ;
     RECT  150.4 389.795 173.815 390.145 ;
     RECT  159.055 330.015 173.84 334.845 ;
     RECT  157.485 340.515 173.84 340.585 ;
     RECT  150.4 357.875 173.84 363.265 ;
     RECT  150.4 371.875 173.84 371.945 ;
     RECT  158.485 377.475 173.84 377.685 ;
     RECT  173.815 386.575 173.84 386.785 ;
     RECT  173.815 389.795 173.84 390.285 ;
     RECT  150.44 45.02 173.88 303.51 ;
     RECT  173.84 321.93 173.88 397.67 ;
     RECT  150.44 416.51 173.88 675 ;
     RECT  173.84 691.53 173.88 714.07 ;
     RECT  173.84 11.13 174.3 28.07 ;
     RECT  173.88 31.15 174.3 714.07 ;
     RECT  174.3 31.15 174.34 712.67 ;
     RECT  174.3 12.53 175.94 28.07 ;
     RECT  175.94 12.53 176.4 29.47 ;
     RECT  174.34 32.55 176.4 712.67 ;
     RECT  176.4 32.55 176.44 318.29 ;
     RECT  176.4 401.73 176.44 687.47 ;
     RECT  176.4 357.875 177.405 363.265 ;
     RECT  176.4 386.575 177.405 386.925 ;
     RECT  177.405 386.575 177.625 386.645 ;
     RECT  177.405 357.875 180.715 357.945 ;
     RECT  177.405 362.915 180.715 363.265 ;
     RECT  180.715 357.875 180.855 363.265 ;
     RECT  180.855 360.395 181.615 363.265 ;
     RECT  176.4 377.475 183.135 377.685 ;
     RECT  182.995 322.035 185.085 322.105 ;
     RECT  182.995 397.915 185.085 397.985 ;
     RECT  176.4 330.015 193.395 334.845 ;
     RECT  176.4 389.795 193.395 390.285 ;
     RECT  176.4 340.515 193.825 340.585 ;
     RECT  193.255 310.695 194.325 310.765 ;
     RECT  193.255 409.255 194.325 409.325 ;
     RECT  193.395 330.015 199.84 332.045 ;
     RECT  193.825 340.515 199.84 343.385 ;
     RECT  181.855 354.935 199.84 355.005 ;
     RECT  181.615 360.395 199.84 362.005 ;
     RECT  176.4 371.875 199.84 371.945 ;
     RECT  183.135 377.475 199.84 377.545 ;
     RECT  193.395 389.935 199.84 390.285 ;
     RECT  176.44 45.02 199.88 303.51 ;
     RECT  199.84 321.93 199.88 397.67 ;
     RECT  176.44 416.51 199.88 675 ;
     RECT  199.84 691.53 199.88 714.07 ;
     RECT  199.84 11.13 200.3 28.07 ;
     RECT  199.88 31.15 200.3 714.07 ;
     RECT  200.3 31.15 200.34 712.67 ;
     RECT  200.3 12.53 201.94 28.07 ;
     RECT  201.94 12.53 202.4 29.47 ;
     RECT  200.34 32.55 202.4 712.67 ;
     RECT  202.4 32.55 202.44 318.29 ;
     RECT  202.4 401.73 202.44 687.47 ;
     RECT  202.4 371.875 203.655 371.945 ;
     RECT  202.4 322.035 203.845 322.105 ;
     RECT  202.4 397.915 203.845 397.985 ;
     RECT  202.4 360.395 209.545 362.005 ;
     RECT  202.4 389.935 213.785 390.285 ;
     RECT  213.225 322.035 213.915 322.105 ;
     RECT  202.4 340.515 213.915 343.385 ;
     RECT  213.785 390 213.915 390.285 ;
     RECT  213.225 397.915 213.915 397.985 ;
     RECT  222.465 319.235 225.84 319.305 ;
     RECT  202.4 330.015 225.84 332.045 ;
     RECT  223.655 337.575 225.84 337.645 ;
     RECT  213.915 343.315 225.84 343.385 ;
     RECT  202.4 354.935 225.84 355.005 ;
     RECT  209.545 360.535 225.84 362.005 ;
     RECT  202.4 377.475 225.84 377.545 ;
     RECT  210.165 385.175 225.84 385.245 ;
     RECT  213.915 390.215 225.84 390.285 ;
     RECT  202.44 45.02 225.88 303.51 ;
     RECT  225.84 319.235 225.88 397.67 ;
     RECT  222.465 400.715 225.88 400.785 ;
     RECT  202.44 416.51 225.88 675 ;
     RECT  225.84 691.53 225.88 714.07 ;
     RECT  225.84 11.13 226.3 28.07 ;
     RECT  225.88 31.15 226.3 714.07 ;
     RECT  226.3 31.15 226.34 712.67 ;
     RECT  226.3 12.53 227.94 28.07 ;
     RECT  227.94 12.53 228.4 29.47 ;
     RECT  226.34 32.55 228.4 712.67 ;
     RECT  228.4 32.55 228.44 318.29 ;
     RECT  228.4 401.73 228.44 687.47 ;
     RECT  228.4 330.015 234.245 330.085 ;
     RECT  231.985 322.035 234.435 322.105 ;
     RECT  228.4 377.475 234.435 377.545 ;
     RECT  231.985 397.915 234.435 397.985 ;
     RECT  228.4 354.935 235.435 355.005 ;
     RECT  235.435 354.935 236.195 356.545 ;
     RECT  236.195 354.935 238.235 358.645 ;
     RECT  238.235 355.915 238.805 358.645 ;
     RECT  238.805 355.915 239.565 356.265 ;
     RECT  228.4 361.935 240.515 362.005 ;
     RECT  228.4 337.575 251.84 337.645 ;
     RECT  239.565 356.195 251.84 356.265 ;
     RECT  228.4 385.175 251.84 385.245 ;
     RECT  228.44 45.02 251.88 303.51 ;
     RECT  251.84 321.93 251.88 397.67 ;
     RECT  228.44 416.51 251.88 675 ;
     RECT  251.84 691.53 251.88 714.07 ;
     RECT  251.84 11.13 252.3 28.07 ;
     RECT  251.88 31.15 252.3 714.07 ;
     RECT  252.3 31.15 252.34 712.67 ;
     RECT  252.3 12.53 253.94 28.07 ;
     RECT  253.94 12.53 254.4 29.47 ;
     RECT  252.34 32.55 254.4 712.67 ;
     RECT  254.4 32.55 254.44 318.29 ;
     RECT  254.4 401.73 254.44 687.47 ;
     RECT  254.44 45.02 261.945 303.51 ;
     RECT  259.145 307.335 261.945 307.405 ;
     RECT  259.145 412.615 261.945 412.685 ;
     RECT  254.44 416.51 261.945 675 ;
     RECT  254.4 337.575 277.84 337.645 ;
     RECT  254.4 356.195 277.84 356.265 ;
     RECT  254.4 385.175 277.84 385.245 ;
     RECT  261.945 45.02 277.88 307.405 ;
     RECT  277.84 321.93 277.88 397.67 ;
     RECT  261.945 412.615 277.88 675 ;
     RECT  277.84 691.53 277.88 714.07 ;
     RECT  277.84 11.13 278.3 28.07 ;
     RECT  277.88 31.15 278.3 714.07 ;
     RECT  278.3 31.15 278.34 712.67 ;
     RECT  278.3 12.53 279.94 28.07 ;
     RECT  279.94 12.53 280.4 29.47 ;
     RECT  278.34 32.55 280.4 712.67 ;
     RECT  280.4 32.55 280.44 318.29 ;
     RECT  280.4 401.73 280.44 687.47 ;
     RECT  280.44 45.02 286.08 307.405 ;
     RECT  280.44 412.615 286.08 675 ;
     RECT  286.08 45.02 286.22 45.72 ;
     RECT  286.08 63.7 286.22 78.66 ;
     RECT  286.08 287.665 286.22 288.04 ;
     RECT  286.08 302.81 286.22 307.405 ;
     RECT  286.08 412.615 286.22 417.21 ;
     RECT  286.08 431.98 286.22 432.355 ;
     RECT  286.08 641.36 286.22 656.32 ;
     RECT  286.08 674.3 286.22 675 ;
     RECT  286.22 287.735 286.41 287.97 ;
     RECT  286.22 432.05 286.41 432.285 ;
     RECT  286.22 73.65 286.69 78.645 ;
     RECT  286.22 641.375 286.69 646.37 ;
     RECT  286.22 68.635 296.805 70.665 ;
     RECT  286.22 649.355 296.805 651.385 ;
     RECT  280.4 337.575 303.84 337.645 ;
     RECT  280.4 356.195 303.84 356.265 ;
     RECT  280.4 385.175 303.84 385.245 ;
     RECT  296.665 55.335 303.88 55.405 ;
     RECT  286.22 63.735 303.88 65.765 ;
     RECT  296.805 70.595 303.88 70.665 ;
     RECT  286.69 73.675 303.88 78.645 ;
     RECT  286.41 287.735 303.88 287.945 ;
     RECT  286.22 305.095 303.88 307.405 ;
     RECT  303.84 321.93 303.88 397.67 ;
     RECT  286.22 412.615 303.88 414.925 ;
     RECT  286.41 432.075 303.88 432.285 ;
     RECT  286.69 641.375 303.88 646.345 ;
     RECT  296.805 649.355 303.88 649.425 ;
     RECT  286.22 654.255 303.88 656.285 ;
     RECT  296.665 664.615 303.88 664.685 ;
     RECT  303.84 691.53 303.88 714.07 ;
     RECT  303.84 11.13 304.3 28.07 ;
     RECT  303.88 31.15 304.3 714.07 ;
     RECT  304.3 31.15 304.34 712.67 ;
     RECT  304.3 12.53 305.94 28.07 ;
     RECT  305.94 12.53 306.4 29.47 ;
     RECT  304.34 32.55 306.4 712.67 ;
     RECT  306.4 32.55 306.44 318.29 ;
     RECT  306.4 401.73 306.44 687.47 ;
     RECT  306.44 412.615 310.825 414.925 ;
     RECT  306.4 385.175 310.965 385.245 ;
     RECT  310.825 412.615 311.005 415.065 ;
     RECT  306.44 70.595 313.655 70.665 ;
     RECT  306.44 649.355 313.655 649.425 ;
     RECT  306.44 63.735 313.725 65.765 ;
     RECT  313.655 70.455 313.725 70.665 ;
     RECT  313.655 649.355 313.725 649.565 ;
     RECT  306.44 654.255 313.725 656.285 ;
     RECT  306.44 73.675 316.265 78.645 ;
     RECT  310.865 426.055 316.265 426.125 ;
     RECT  306.44 641.375 316.265 646.345 ;
     RECT  313.725 63.735 316.405 65.485 ;
     RECT  316.265 73.675 316.405 80.605 ;
     RECT  306.44 287.735 316.405 287.945 ;
     RECT  306.44 305.095 316.405 307.405 ;
     RECT  311.005 412.615 316.405 414.925 ;
     RECT  306.44 432.075 316.405 432.285 ;
     RECT  316.265 639.415 316.405 646.345 ;
     RECT  313.725 654.535 316.405 656.285 ;
     RECT  316.405 307.335 316.705 307.405 ;
     RECT  306.4 337.575 316.845 337.645 ;
     RECT  316.705 307.335 316.895 307.825 ;
     RECT  316.265 426.055 319.365 427.805 ;
     RECT  316.755 302.015 319.625 302.085 ;
     RECT  316.405 287.735 319.66 287.805 ;
     RECT  316.405 432.215 319.66 432.285 ;
     RECT  316.405 78.575 319.765 80.605 ;
     RECT  316.405 639.415 319.765 641.445 ;
     RECT  316.265 60.375 319.785 60.445 ;
     RECT  316.405 75.495 319.785 75.565 ;
     RECT  316.265 292.215 319.795 292.285 ;
     RECT  319.765 639.415 319.795 639.485 ;
     RECT  316.405 654.535 319.795 654.605 ;
     RECT  319.625 302.015 319.935 302.365 ;
     RECT  316.405 65.415 319.97 65.485 ;
     RECT  313.725 70.455 319.97 70.525 ;
     RECT  319.765 80.535 319.97 80.605 ;
     RECT  319.625 85.575 319.97 85.645 ;
     RECT  316.265 297.255 319.97 297.325 ;
     RECT  319.935 302.295 319.97 302.365 ;
     RECT  316.895 307.335 319.97 307.405 ;
     RECT  313.725 649.495 319.97 649.565 ;
     RECT  316.265 659.575 319.97 659.645 ;
     RECT  319.785 60.375 320.04 60.585 ;
     RECT  319.97 65.415 320.04 65.625 ;
     RECT  319.97 70.455 320.04 70.665 ;
     RECT  319.97 80.535 320.04 80.745 ;
     RECT  319.97 85.575 320.04 85.785 ;
     RECT  319.66 287.175 320.04 287.805 ;
     RECT  319.795 292.215 320.04 293.125 ;
     RECT  319.97 297.255 320.04 297.465 ;
     RECT  319.97 302.295 320.04 302.645 ;
     RECT  319.97 307.335 320.04 307.545 ;
     RECT  319.365 426.895 320.04 427.805 ;
     RECT  319.66 432.215 320.04 432.845 ;
     RECT  319.795 638.155 320.04 639.485 ;
     RECT  319.97 649.355 320.04 649.565 ;
     RECT  319.795 653.835 320.04 654.605 ;
     RECT  319.97 659.435 320.04 659.645 ;
     RECT  320.04 659.435 320.125 659.505 ;
     RECT  320.04 649.355 320.205 649.425 ;
     RECT  320.04 85.715 320.345 85.785 ;
     RECT  320.04 297.395 320.345 297.465 ;
     RECT  319.985 360.535 320.365 360.605 ;
     RECT  306.44 55.335 320.38 55.405 ;
     RECT  320.38 55.335 320.485 55.545 ;
     RECT  316.405 412.615 320.485 412.685 ;
     RECT  319.625 634.375 320.485 634.445 ;
     RECT  319.785 75.495 320.505 77.105 ;
     RECT  320.345 85.715 320.505 85.925 ;
     RECT  320.345 297.395 320.695 299.285 ;
     RECT  320.04 638.155 320.765 638.505 ;
     RECT  306.44 664.615 320.765 664.685 ;
     RECT  306.4 356.195 321.185 356.265 ;
     RECT  321.185 354.795 321.325 356.265 ;
     RECT  320.365 360.535 321.325 360.885 ;
     RECT  320.765 638.155 321.885 638.365 ;
     RECT  324.825 333.375 325.255 333.445 ;
     RECT  320.505 75.495 325.42 75.565 ;
     RECT  325.42 75.495 325.525 75.845 ;
     RECT  316.405 644.455 325.525 644.525 ;
     RECT  320.04 287.175 325.635 287.245 ;
     RECT  320.04 432.775 325.635 432.845 ;
     RECT  321.885 638.295 325.805 638.365 ;
     RECT  320.345 629.755 326.085 629.825 ;
     RECT  316.265 422.695 326.365 422.765 ;
     RECT  319.625 417.655 326.645 417.725 ;
     RECT  320.485 55.475 329.84 55.545 ;
     RECT  320.04 60.515 329.84 60.585 ;
     RECT  320.04 65.555 329.84 65.625 ;
     RECT  320.04 70.595 329.84 70.665 ;
     RECT  325.525 75.775 329.84 75.845 ;
     RECT  320.04 80.675 329.84 80.745 ;
     RECT  320.505 85.715 329.84 85.785 ;
     RECT  320.695 297.395 329.84 297.465 ;
     RECT  320.04 302.575 329.84 302.645 ;
     RECT  320.04 307.475 329.84 307.545 ;
     RECT  321.325 354.795 329.84 354.865 ;
     RECT  321.325 360.815 329.84 360.885 ;
     RECT  325.115 391.335 329.84 391.405 ;
     RECT  329.84 11.13 330.3 714.07 ;
     RECT  330.3 12.53 332.4 712.67 ;
     RECT  332.4 55.475 355.84 55.545 ;
     RECT  332.4 60.515 355.84 60.585 ;
     RECT  332.4 65.555 355.84 65.625 ;
     RECT  332.4 70.595 355.84 70.665 ;
     RECT  332.4 75.775 355.84 75.845 ;
     RECT  332.4 80.675 355.84 80.745 ;
     RECT  332.4 85.715 355.84 85.785 ;
     RECT  332.4 297.395 355.84 297.465 ;
     RECT  332.4 302.575 355.84 302.645 ;
     RECT  332.4 307.475 355.84 307.545 ;
     RECT  332.4 354.795 355.84 354.865 ;
     RECT  355.84 11.13 356.3 714.07 ;
     RECT  356.3 12.53 358.4 712.67 ;
     RECT  358.4 75.775 369.66 75.845 ;
     RECT  358.4 302.575 369.66 302.645 ;
     RECT  369.66 75.635 369.73 75.845 ;
     RECT  369.66 302.435 369.73 302.645 ;
     RECT  358.4 354.795 369.765 354.865 ;
     RECT  358.4 55.475 369.965 55.545 ;
     RECT  358.4 60.515 369.965 60.585 ;
     RECT  358.4 65.555 369.965 65.625 ;
     RECT  358.4 70.595 369.965 70.665 ;
     RECT  369.73 75.635 369.965 75.705 ;
     RECT  358.4 80.675 369.965 80.745 ;
     RECT  358.4 85.715 369.965 85.785 ;
     RECT  369.625 287.315 369.965 287.385 ;
     RECT  358.4 297.395 369.965 297.465 ;
     RECT  369.73 302.435 369.965 302.505 ;
     RECT  358.4 307.475 369.965 307.545 ;
    LAYER metal4 ;
     RECT  17.82 11.13 18.32 11.16 ;
     RECT  43.82 11.13 44.32 11.16 ;
     RECT  69.82 11.13 70.32 11.16 ;
     RECT  95.82 11.13 96.32 11.16 ;
     RECT  121.82 11.13 122.32 11.16 ;
     RECT  147.82 11.13 148.32 11.16 ;
     RECT  173.82 11.13 174.32 11.16 ;
     RECT  199.82 11.13 200.32 11.16 ;
     RECT  225.82 11.13 226.32 11.16 ;
     RECT  251.82 11.13 252.32 11.16 ;
     RECT  277.82 11.13 278.32 11.16 ;
     RECT  303.82 11.13 304.32 11.16 ;
     RECT  329.82 11.13 330.32 11.16 ;
     RECT  355.82 11.13 356.32 11.16 ;
     RECT  69.82 11.16 72.42 30.43 ;
     RECT  95.82 11.16 98.42 30.43 ;
     RECT  121.82 11.16 124.42 30.43 ;
     RECT  147.82 11.16 150.42 30.43 ;
     RECT  173.82 11.16 176.42 30.43 ;
     RECT  199.82 11.16 202.42 30.43 ;
     RECT  225.82 11.16 228.42 30.43 ;
     RECT  251.82 11.16 254.42 30.43 ;
     RECT  277.82 11.16 280.42 30.43 ;
     RECT  303.82 11.16 306.42 30.43 ;
     RECT  69.86 30.43 72.42 31.18 ;
     RECT  95.86 30.43 98.42 31.18 ;
     RECT  121.86 30.43 124.42 31.18 ;
     RECT  147.86 30.43 150.42 31.18 ;
     RECT  173.86 30.43 176.42 31.18 ;
     RECT  199.86 30.43 202.42 31.18 ;
     RECT  225.86 30.43 228.42 31.18 ;
     RECT  251.86 30.43 254.42 31.18 ;
     RECT  277.86 30.43 280.42 31.18 ;
     RECT  303.86 30.43 306.42 31.18 ;
     RECT  121.86 31.18 124.46 35.14 ;
     RECT  69.86 31.18 72.46 41.72 ;
     RECT  121.86 35.14 126.565 41.72 ;
     RECT  132.305 41.58 132.445 41.72 ;
     RECT  81.905 41.58 82.045 41.86 ;
     RECT  69.86 41.72 75.605 42 ;
     RECT  81.345 41.86 82.045 42 ;
     RECT  121.86 41.72 132.445 42.14 ;
     RECT  120.825 42.14 132.445 42.56 ;
     RECT  138.185 30.1 138.325 42.56 ;
     RECT  114.945 40.18 115.085 42.7 ;
     RECT  120.825 42.56 138.325 42.7 ;
     RECT  114.945 42.7 140.845 43.54 ;
     RECT  106.545 41.86 106.685 44.38 ;
     RECT  114.945 43.54 141.005 44.38 ;
     RECT  69.86 42 82.045 45.02 ;
     RECT  277.86 31.18 280.46 45.02 ;
     RECT  69.86 45.02 85.975 45.16 ;
     RECT  95.86 31.18 98.46 45.16 ;
     RECT  106.545 44.38 141.005 45.16 ;
     RECT  147.86 31.18 150.46 45.16 ;
     RECT  173.86 31.18 176.46 45.16 ;
     RECT  199.86 31.18 202.46 45.16 ;
     RECT  225.86 31.18 228.46 45.16 ;
     RECT  251.86 31.18 254.46 45.16 ;
     RECT  277.86 45.02 286.22 45.16 ;
     RECT  320.345 55.3 320.485 60.34 ;
     RECT  316.265 60.34 320.485 63.84 ;
     RECT  319.785 63.84 320.485 65.52 ;
     RECT  296.665 55.3 296.805 68.74 ;
     RECT  60.225 65.24 60.365 71.26 ;
     RECT  60.225 71.26 64.005 71.4 ;
     RECT  319.785 65.52 321.885 73.64 ;
     RECT  316.265 73.64 321.885 75.46 ;
     RECT  329.82 11.16 332.42 75.46 ;
     RECT  69.86 45.16 286.22 80.64 ;
     RECT  316.265 75.46 332.42 80.64 ;
     RECT  319.625 80.64 332.42 85.68 ;
     RECT  78.265 80.64 286.22 90.72 ;
     RECT  81.345 90.72 286.22 100.8 ;
     RECT  69.86 80.64 72.46 105.7 ;
     RECT  63.865 71.4 64.005 105.84 ;
     RECT  69.86 105.7 77.285 110.74 ;
     RECT  61.905 105.84 64.005 110.88 ;
     RECT  69.86 110.74 77.565 113.54 ;
     RECT  61.625 110.88 64.005 115.92 ;
     RECT  85.275 100.8 286.22 118.3 ;
     RECT  60.505 115.92 64.005 123.2 ;
     RECT  60.065 123.2 64.005 131.04 ;
     RECT  81.345 118.3 286.22 136.08 ;
     RECT  320.065 85.68 332.42 287.84 ;
     RECT  85.275 136.08 286.22 303.37 ;
     RECT  85.275 303.37 85.975 303.51 ;
     RECT  251.86 303.37 262.095 303.51 ;
     RECT  277.86 303.37 286.22 303.51 ;
     RECT  184.865 303.37 185.085 303.8 ;
     RECT  136.605 303.37 136.925 304.92 ;
     RECT  146.005 303.37 155.685 304.92 ;
     RECT  213.065 303.37 213.365 304.92 ;
     RECT  251.86 303.51 262.085 305.2 ;
     RECT  316.265 287.84 332.42 305.2 ;
     RECT  251.86 305.2 259.285 307.44 ;
     RECT  194.185 303.37 203.845 310.8 ;
     RECT  136.785 304.92 136.925 319.34 ;
     RECT  222.465 303.37 232.125 319.34 ;
     RECT  69.86 113.54 72.46 319.66 ;
     RECT  95.86 303.37 98.46 319.66 ;
     RECT  173.86 303.37 176.46 319.66 ;
     RECT  251.86 307.44 254.46 319.66 ;
     RECT  277.86 303.51 280.46 319.66 ;
     RECT  303.86 31.18 306.46 319.66 ;
     RECT  69.86 319.66 72.42 320.23 ;
     RECT  95.86 319.66 98.42 320.23 ;
     RECT  121.86 303.37 127.405 320.23 ;
     RECT  173.86 319.66 176.42 320.23 ;
     RECT  199.86 310.8 203.845 320.23 ;
     RECT  251.86 319.66 254.42 320.23 ;
     RECT  277.86 319.66 280.42 320.23 ;
     RECT  303.86 319.66 306.42 320.23 ;
     RECT  121.82 320.23 127.405 322.14 ;
     RECT  146.025 304.92 155.685 322.14 ;
     RECT  184.945 303.8 185.085 322.14 ;
     RECT  199.82 320.23 203.845 322.14 ;
     RECT  213.225 304.92 213.365 322.14 ;
     RECT  225.82 319.34 232.125 322.14 ;
     RECT  60.505 131.04 64.005 333.62 ;
     RECT  173.82 320.23 176.42 333.76 ;
     RECT  316.705 305.2 332.42 337.68 ;
     RECT  173.82 333.76 177.685 353.47 ;
     RECT  369.625 287.28 369.765 354.9 ;
     RECT  303.82 320.23 306.42 385.14 ;
     RECT  60.505 333.62 62.045 386.68 ;
     RECT  173.82 353.47 177.405 386.96 ;
     RECT  121.82 322.14 124.42 397.88 ;
     RECT  147.82 322.14 150.42 397.88 ;
     RECT  199.82 322.14 202.42 397.88 ;
     RECT  225.82 322.14 228.42 397.88 ;
     RECT  69.82 320.23 72.42 399.79 ;
     RECT  95.82 320.23 98.42 399.79 ;
     RECT  121.82 397.88 127.405 399.79 ;
     RECT  173.82 386.96 176.42 399.79 ;
     RECT  199.82 397.88 203.845 399.79 ;
     RECT  251.82 320.23 254.42 399.79 ;
     RECT  277.82 320.23 280.42 399.79 ;
     RECT  303.82 385.14 310.965 399.79 ;
     RECT  69.86 399.79 72.42 400.36 ;
     RECT  95.86 399.79 98.42 400.36 ;
     RECT  173.86 399.79 176.42 400.36 ;
     RECT  251.86 399.79 254.42 400.36 ;
     RECT  277.86 399.79 280.42 400.36 ;
     RECT  225.82 397.88 232.125 400.68 ;
     RECT  199.86 399.79 203.845 409.22 ;
     RECT  251.86 400.36 254.46 412.58 ;
     RECT  251.86 412.58 259.285 414.82 ;
     RECT  303.86 399.79 310.965 414.82 ;
     RECT  320.065 337.68 332.42 414.82 ;
     RECT  136.785 400.68 136.925 415.1 ;
     RECT  146.025 397.88 155.685 415.1 ;
     RECT  213.225 397.88 213.365 415.1 ;
     RECT  303.86 414.82 332.42 415.1 ;
     RECT  184.945 397.88 185.085 416.22 ;
     RECT  251.86 414.82 262.085 416.51 ;
     RECT  277.86 400.36 280.46 416.51 ;
     RECT  85.275 416.51 85.975 416.65 ;
     RECT  95.86 400.36 98.46 416.65 ;
     RECT  121.86 399.79 127.405 416.65 ;
     RECT  136.605 415.1 136.925 416.65 ;
     RECT  146.005 415.1 155.685 416.65 ;
     RECT  173.86 400.36 176.46 416.65 ;
     RECT  184.865 416.22 185.085 416.65 ;
     RECT  194.185 409.22 203.845 416.65 ;
     RECT  213.065 415.1 213.365 416.65 ;
     RECT  222.465 400.68 232.125 416.65 ;
     RECT  251.86 416.51 262.095 416.65 ;
     RECT  277.86 416.51 286.22 416.65 ;
     RECT  316.265 415.1 332.42 432.18 ;
     RECT  85.275 416.65 286.22 583.94 ;
     RECT  60.505 386.68 64.005 588.98 ;
     RECT  60.065 588.98 64.005 596.82 ;
     RECT  81.345 583.94 286.22 601.72 ;
     RECT  60.505 596.82 64.005 603.54 ;
     RECT  69.86 400.36 72.46 606.48 ;
     RECT  69.86 606.48 77.565 609.28 ;
     RECT  61.065 603.54 64.005 614.18 ;
     RECT  69.86 609.28 77.285 614.32 ;
     RECT  85.275 601.72 286.22 619.22 ;
     RECT  81.345 619.22 286.22 629.3 ;
     RECT  320.065 432.18 332.42 634.34 ;
     RECT  63.865 614.18 64.005 638.26 ;
     RECT  60.225 638.26 64.005 638.4 ;
     RECT  69.86 614.32 72.46 639.38 ;
     RECT  78.265 629.3 286.22 639.38 ;
     RECT  319.625 634.34 332.42 639.38 ;
     RECT  316.265 639.38 332.42 644.56 ;
     RECT  316.265 644.56 320.765 646.38 ;
     RECT  320.065 646.38 320.765 649.46 ;
     RECT  0.025 360.5 0.165 650.3 ;
     RECT  60.225 638.4 60.365 654.5 ;
     RECT  320.625 649.46 320.765 656.18 ;
     RECT  316.265 656.18 320.765 659.68 ;
     RECT  296.665 651.28 296.805 664.72 ;
     RECT  320.625 659.68 320.765 664.72 ;
     RECT  69.86 639.38 286.22 674.86 ;
     RECT  69.86 674.86 85.975 675 ;
     RECT  277.86 674.86 286.22 675 ;
     RECT  106.545 674.86 141.005 675.64 ;
     RECT  114.945 675.64 141.005 676.48 ;
     RECT  114.945 676.48 140.845 677.32 ;
     RECT  120.825 677.32 138.325 677.46 ;
     RECT  120.825 677.46 132.445 677.88 ;
     RECT  69.86 675 82.045 678.02 ;
     RECT  81.345 678.02 82.045 678.16 ;
     RECT  106.545 675.64 106.685 678.16 ;
     RECT  69.86 678.02 75.605 678.3 ;
     RECT  121.86 677.88 132.445 678.3 ;
     RECT  81.905 678.16 82.045 678.44 ;
     RECT  132.305 678.3 132.445 678.44 ;
     RECT  114.945 677.32 115.085 679.84 ;
     RECT  121.86 678.3 126.565 684.88 ;
     RECT  69.86 678.3 72.46 688.84 ;
     RECT  95.86 674.86 98.46 688.84 ;
     RECT  121.86 684.88 124.46 688.84 ;
     RECT  147.86 674.86 150.46 688.84 ;
     RECT  173.86 674.86 176.46 688.84 ;
     RECT  199.86 674.86 202.46 688.84 ;
     RECT  225.86 674.86 228.46 688.84 ;
     RECT  251.86 674.86 254.46 688.84 ;
     RECT  277.86 675 280.46 688.84 ;
     RECT  303.86 415.1 306.46 688.84 ;
     RECT  69.86 688.84 72.42 689.59 ;
     RECT  95.86 688.84 98.42 689.59 ;
     RECT  121.86 688.84 124.42 689.59 ;
     RECT  147.86 688.84 150.42 689.59 ;
     RECT  173.86 688.84 176.42 689.59 ;
     RECT  199.86 688.84 202.42 689.59 ;
     RECT  225.86 688.84 228.42 689.59 ;
     RECT  251.86 688.84 254.42 689.59 ;
     RECT  277.86 688.84 280.42 689.59 ;
     RECT  303.86 688.84 306.42 689.59 ;
     RECT  138.185 677.46 138.325 689.92 ;
     RECT  17.82 11.16 20.42 714.04 ;
     RECT  43.82 11.16 46.42 714.04 ;
     RECT  69.82 689.59 72.42 714.04 ;
     RECT  95.82 689.59 98.42 714.04 ;
     RECT  121.82 689.59 124.42 714.04 ;
     RECT  147.82 689.59 150.42 714.04 ;
     RECT  173.82 689.59 176.42 714.04 ;
     RECT  199.82 689.59 202.42 714.04 ;
     RECT  225.82 689.59 228.42 714.04 ;
     RECT  251.82 689.59 254.42 714.04 ;
     RECT  277.82 689.59 280.42 714.04 ;
     RECT  303.82 689.59 306.42 714.04 ;
     RECT  329.82 644.56 332.42 714.04 ;
     RECT  355.82 11.16 358.42 714.04 ;
     RECT  17.82 714.04 18.32 714.07 ;
     RECT  43.82 714.04 44.32 714.07 ;
     RECT  69.82 714.04 70.32 714.07 ;
     RECT  95.82 714.04 96.32 714.07 ;
     RECT  121.82 714.04 122.32 714.07 ;
     RECT  147.82 714.04 148.32 714.07 ;
     RECT  173.82 714.04 174.32 714.07 ;
     RECT  199.82 714.04 200.32 714.07 ;
     RECT  225.82 714.04 226.32 714.07 ;
     RECT  251.82 714.04 252.32 714.07 ;
     RECT  277.82 714.04 278.32 714.07 ;
     RECT  303.82 714.04 304.32 714.07 ;
     RECT  329.82 714.04 330.32 714.07 ;
     RECT  355.82 714.04 356.32 714.07 ;
    LAYER metal5 ;
     RECT  10.07 81.95 69.32 84.55 ;
     RECT  10.07 291.95 69.57 294.55 ;
     RECT  10.07 51.95 69.86 54.55 ;
     RECT  10.07 111.95 69.86 114.55 ;
     RECT  10.07 231.95 69.86 234.55 ;
     RECT  10.07 261.95 69.86 264.55 ;
     RECT  69.57 291.95 69.86 293.57 ;
     RECT  10.07 321.95 69.86 324.55 ;
     RECT  10.07 501.95 69.86 504.55 ;
     RECT  10.07 561.95 69.86 564.55 ;
     RECT  10.07 681.95 69.86 684.55 ;
     RECT  69.86 30.97 70.11 31.47 ;
     RECT  69.86 51.95 70.11 57.47 ;
     RECT  69.32 82.97 70.11 84.55 ;
     RECT  69.86 134.97 70.11 135.47 ;
     RECT  10.07 141.95 70.11 144.55 ;
     RECT  69.86 160.97 70.11 161.47 ;
     RECT  69.86 186.97 70.11 187.47 ;
     RECT  69.86 212.97 70.11 213.47 ;
     RECT  69.86 231.95 70.11 239.47 ;
     RECT  69.86 261.95 70.11 265.47 ;
     RECT  69.86 402.55 70.11 403.05 ;
     RECT  69.86 428.55 70.11 429.05 ;
     RECT  69.86 454.55 70.11 455.05 ;
     RECT  10.07 471.95 70.11 474.55 ;
     RECT  69.86 480.55 70.11 481.05 ;
     RECT  10.07 531.95 70.11 534.55 ;
     RECT  69.86 558.55 70.11 564.55 ;
     RECT  69.86 584.55 70.11 585.05 ;
     RECT  69.86 610.55 70.11 611.05 ;
     RECT  69.86 636.55 70.11 637.05 ;
     RECT  69.86 662.55 70.11 663.05 ;
     RECT  77.145 44.66 79.945 44.8 ;
     RECT  77.145 675.22 79.945 675.36 ;
     RECT  79.945 44.38 80.225 44.8 ;
     RECT  79.945 675.22 80.225 675.64 ;
     RECT  69.86 681.95 80.225 689.05 ;
     RECT  80.225 42.7 109.545 44.8 ;
     RECT  80.225 675.22 109.545 689.05 ;
     RECT  109.545 42.7 112.405 44.52 ;
     RECT  109.545 675.5 112.405 689.05 ;
     RECT  112.405 42.7 118.165 42.84 ;
     RECT  112.405 677.18 118.165 689.05 ;
     RECT  10.07 411.95 256.345 414.55 ;
     RECT  70.11 30.97 309.89 33.57 ;
     RECT  70.11 51.95 309.89 59.57 ;
     RECT  70.11 82.97 309.89 85.57 ;
     RECT  69.86 108.97 309.89 114.55 ;
     RECT  70.11 134.97 309.89 144.55 ;
     RECT  70.11 160.97 309.89 163.57 ;
     RECT  70.11 186.97 309.89 189.57 ;
     RECT  70.11 212.97 309.89 215.57 ;
     RECT  70.11 231.95 309.89 241.57 ;
     RECT  70.11 261.95 309.89 267.57 ;
     RECT  69.86 290.97 309.89 293.57 ;
     RECT  69.86 316.97 309.89 324.55 ;
     RECT  70.11 400.45 309.89 403.05 ;
     RECT  70.11 426.45 309.89 429.05 ;
     RECT  70.11 452.45 309.89 455.05 ;
     RECT  70.11 471.95 309.89 481.05 ;
     RECT  69.86 501.95 309.89 507.05 ;
     RECT  70.11 530.45 309.89 534.55 ;
     RECT  70.11 556.45 309.89 564.55 ;
     RECT  70.11 582.45 309.89 585.05 ;
     RECT  70.11 608.45 309.89 611.05 ;
     RECT  70.11 634.45 309.89 637.05 ;
     RECT  70.11 660.45 309.89 663.05 ;
     RECT  118.165 681.95 309.89 689.05 ;
     RECT  309.89 82.97 310.43 84.55 ;
     RECT  309.89 291.95 310.43 293.57 ;
     RECT  256.345 305.06 319.765 305.2 ;
     RECT  256.345 411.95 319.765 414.96 ;
     RECT  324.825 333.48 327.205 333.62 ;
     RECT  45.92 701.5 332.42 702 ;
     RECT  10.07 21.95 359.86 24.55 ;
     RECT  309.89 51.95 359.86 54.55 ;
     RECT  310.43 81.95 359.86 84.55 ;
     RECT  309.89 111.95 359.86 114.55 ;
     RECT  309.89 141.95 359.86 144.55 ;
     RECT  10.07 171.95 359.86 174.55 ;
     RECT  10.07 201.95 359.86 204.55 ;
     RECT  309.89 231.95 359.86 234.55 ;
     RECT  309.89 261.95 359.86 264.55 ;
     RECT  310.43 291.95 359.86 294.55 ;
     RECT  309.89 321.95 359.86 324.55 ;
     RECT  10.07 351.95 359.86 354.55 ;
     RECT  10.07 381.95 359.86 384.55 ;
     RECT  319.765 411.95 359.86 414.55 ;
     RECT  10.07 441.95 359.86 444.55 ;
     RECT  309.89 471.95 359.86 474.55 ;
     RECT  309.89 501.95 359.86 504.55 ;
     RECT  309.89 531.95 359.86 534.55 ;
     RECT  309.89 561.95 359.86 564.55 ;
     RECT  10.07 591.95 359.86 594.55 ;
     RECT  10.07 621.95 359.86 624.55 ;
     RECT  10.07 651.95 359.86 654.55 ;
     RECT  309.89 681.95 359.86 684.55 ;
     RECT  10.07 711.95 359.86 712.45 ;
  END
END SRAM20x2048
END LIBRARY
